VERSION 5.7 ;
BUSBITCHARS "[]" ;
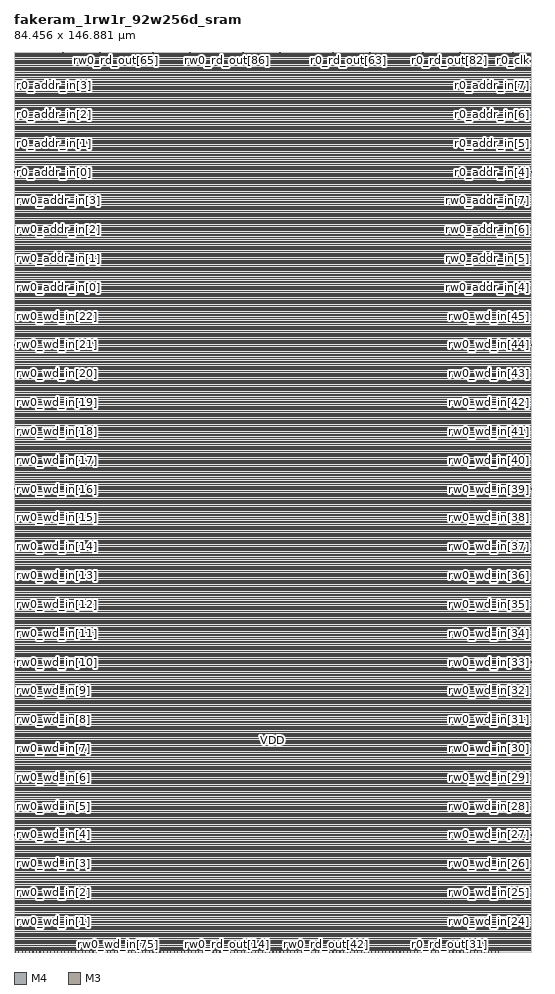
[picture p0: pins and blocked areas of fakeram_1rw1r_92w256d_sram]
MACRO fakeram_1rw1r_92w256d_sram
  FOREIGN fakeram_1rw1r_92w256d_sram 0 0 ;
  SYMMETRY X Y R90 ;
  SIZE 84.456 BY 146.881 ;
  CLASS BLOCK ;
  PIN rw0_wd_in[0]
    DIRECTION INPUT ;
    USE SIGNAL ;
    SHAPE ABUTMENT ;
    PORT
      LAYER M4 ;
      RECT 0.000 0.276 0.072 0.300 ;
    END
  END rw0_wd_in[0]
  PIN rw0_wd_in[1]
    DIRECTION INPUT ;
    USE SIGNAL ;
    SHAPE ABUTMENT ;
    PORT
      LAYER M4 ;
      RECT 0.000 4.980 0.072 5.004 ;
    END
  END rw0_wd_in[1]
  PIN rw0_wd_in[2]
    DIRECTION INPUT ;
    USE SIGNAL ;
    SHAPE ABUTMENT ;
    PORT
      LAYER M4 ;
      RECT 0.000 9.684 0.072 9.708 ;
    END
  END rw0_wd_in[2]
  PIN rw0_wd_in[3]
    DIRECTION INPUT ;
    USE SIGNAL ;
    SHAPE ABUTMENT ;
    PORT
      LAYER M4 ;
      RECT 0.000 14.388 0.072 14.412 ;
    END
  END rw0_wd_in[3]
  PIN rw0_wd_in[4]
    DIRECTION INPUT ;
    USE SIGNAL ;
    SHAPE ABUTMENT ;
    PORT
      LAYER M4 ;
      RECT 0.000 19.092 0.072 19.116 ;
    END
  END rw0_wd_in[4]
  PIN rw0_wd_in[5]
    DIRECTION INPUT ;
    USE SIGNAL ;
    SHAPE ABUTMENT ;
    PORT
      LAYER M4 ;
      RECT 0.000 23.796 0.072 23.820 ;
    END
  END rw0_wd_in[5]
  PIN rw0_wd_in[6]
    DIRECTION INPUT ;
    USE SIGNAL ;
    SHAPE ABUTMENT ;
    PORT
      LAYER M4 ;
      RECT 0.000 28.500 0.072 28.524 ;
    END
  END rw0_wd_in[6]
  PIN rw0_wd_in[7]
    DIRECTION INPUT ;
    USE SIGNAL ;
    SHAPE ABUTMENT ;
    PORT
      LAYER M4 ;
      RECT 0.000 33.204 0.072 33.228 ;
    END
  END rw0_wd_in[7]
  PIN rw0_wd_in[8]
    DIRECTION INPUT ;
    USE SIGNAL ;
    SHAPE ABUTMENT ;
    PORT
      LAYER M4 ;
      RECT 0.000 37.908 0.072 37.932 ;
    END
  END rw0_wd_in[8]
  PIN rw0_wd_in[9]
    DIRECTION INPUT ;
    USE SIGNAL ;
    SHAPE ABUTMENT ;
    PORT
      LAYER M4 ;
      RECT 0.000 42.612 0.072 42.636 ;
    END
  END rw0_wd_in[9]
  PIN rw0_wd_in[10]
    DIRECTION INPUT ;
    USE SIGNAL ;
    SHAPE ABUTMENT ;
    PORT
      LAYER M4 ;
      RECT 0.000 47.316 0.072 47.340 ;
    END
  END rw0_wd_in[10]
  PIN rw0_wd_in[11]
    DIRECTION INPUT ;
    USE SIGNAL ;
    SHAPE ABUTMENT ;
    PORT
      LAYER M4 ;
      RECT 0.000 52.020 0.072 52.044 ;
    END
  END rw0_wd_in[11]
  PIN rw0_wd_in[12]
    DIRECTION INPUT ;
    USE SIGNAL ;
    SHAPE ABUTMENT ;
    PORT
      LAYER M4 ;
      RECT 0.000 56.724 0.072 56.748 ;
    END
  END rw0_wd_in[12]
  PIN rw0_wd_in[13]
    DIRECTION INPUT ;
    USE SIGNAL ;
    SHAPE ABUTMENT ;
    PORT
      LAYER M4 ;
      RECT 0.000 61.428 0.072 61.452 ;
    END
  END rw0_wd_in[13]
  PIN rw0_wd_in[14]
    DIRECTION INPUT ;
    USE SIGNAL ;
    SHAPE ABUTMENT ;
    PORT
      LAYER M4 ;
      RECT 0.000 66.132 0.072 66.156 ;
    END
  END rw0_wd_in[14]
  PIN rw0_wd_in[15]
    DIRECTION INPUT ;
    USE SIGNAL ;
    SHAPE ABUTMENT ;
    PORT
      LAYER M4 ;
      RECT 0.000 70.836 0.072 70.860 ;
    END
  END rw0_wd_in[15]
  PIN rw0_wd_in[16]
    DIRECTION INPUT ;
    USE SIGNAL ;
    SHAPE ABUTMENT ;
    PORT
      LAYER M4 ;
      RECT 0.000 75.540 0.072 75.564 ;
    END
  END rw0_wd_in[16]
  PIN rw0_wd_in[17]
    DIRECTION INPUT ;
    USE SIGNAL ;
    SHAPE ABUTMENT ;
    PORT
      LAYER M4 ;
      RECT 0.000 80.244 0.072 80.268 ;
    END
  END rw0_wd_in[17]
  PIN rw0_wd_in[18]
    DIRECTION INPUT ;
    USE SIGNAL ;
    SHAPE ABUTMENT ;
    PORT
      LAYER M4 ;
      RECT 0.000 84.948 0.072 84.972 ;
    END
  END rw0_wd_in[18]
  PIN rw0_wd_in[19]
    DIRECTION INPUT ;
    USE SIGNAL ;
    SHAPE ABUTMENT ;
    PORT
      LAYER M4 ;
      RECT 0.000 89.652 0.072 89.676 ;
    END
  END rw0_wd_in[19]
  PIN rw0_wd_in[20]
    DIRECTION INPUT ;
    USE SIGNAL ;
    SHAPE ABUTMENT ;
    PORT
      LAYER M4 ;
      RECT 0.000 94.356 0.072 94.380 ;
    END
  END rw0_wd_in[20]
  PIN rw0_wd_in[21]
    DIRECTION INPUT ;
    USE SIGNAL ;
    SHAPE ABUTMENT ;
    PORT
      LAYER M4 ;
      RECT 0.000 99.060 0.072 99.084 ;
    END
  END rw0_wd_in[21]
  PIN rw0_wd_in[22]
    DIRECTION INPUT ;
    USE SIGNAL ;
    SHAPE ABUTMENT ;
    PORT
      LAYER M4 ;
      RECT 0.000 103.764 0.072 103.788 ;
    END
  END rw0_wd_in[22]
  PIN rw0_wd_in[23]
    DIRECTION INPUT ;
    USE SIGNAL ;
    SHAPE ABUTMENT ;
    PORT
      LAYER M4 ;
      RECT 84.384 0.276 84.456 0.300 ;
    END
  END rw0_wd_in[23]
  PIN rw0_wd_in[24]
    DIRECTION INPUT ;
    USE SIGNAL ;
    SHAPE ABUTMENT ;
    PORT
      LAYER M4 ;
      RECT 84.384 4.980 84.456 5.004 ;
    END
  END rw0_wd_in[24]
  PIN rw0_wd_in[25]
    DIRECTION INPUT ;
    USE SIGNAL ;
    SHAPE ABUTMENT ;
    PORT
      LAYER M4 ;
      RECT 84.384 9.684 84.456 9.708 ;
    END
  END rw0_wd_in[25]
  PIN rw0_wd_in[26]
    DIRECTION INPUT ;
    USE SIGNAL ;
    SHAPE ABUTMENT ;
    PORT
      LAYER M4 ;
      RECT 84.384 14.388 84.456 14.412 ;
    END
  END rw0_wd_in[26]
  PIN rw0_wd_in[27]
    DIRECTION INPUT ;
    USE SIGNAL ;
    SHAPE ABUTMENT ;
    PORT
      LAYER M4 ;
      RECT 84.384 19.092 84.456 19.116 ;
    END
  END rw0_wd_in[27]
  PIN rw0_wd_in[28]
    DIRECTION INPUT ;
    USE SIGNAL ;
    SHAPE ABUTMENT ;
    PORT
      LAYER M4 ;
      RECT 84.384 23.796 84.456 23.820 ;
    END
  END rw0_wd_in[28]
  PIN rw0_wd_in[29]
    DIRECTION INPUT ;
    USE SIGNAL ;
    SHAPE ABUTMENT ;
    PORT
      LAYER M4 ;
      RECT 84.384 28.500 84.456 28.524 ;
    END
  END rw0_wd_in[29]
  PIN rw0_wd_in[30]
    DIRECTION INPUT ;
    USE SIGNAL ;
    SHAPE ABUTMENT ;
    PORT
      LAYER M4 ;
      RECT 84.384 33.204 84.456 33.228 ;
    END
  END rw0_wd_in[30]
  PIN rw0_wd_in[31]
    DIRECTION INPUT ;
    USE SIGNAL ;
    SHAPE ABUTMENT ;
    PORT
      LAYER M4 ;
      RECT 84.384 37.908 84.456 37.932 ;
    END
  END rw0_wd_in[31]
  PIN rw0_wd_in[32]
    DIRECTION INPUT ;
    USE SIGNAL ;
    SHAPE ABUTMENT ;
    PORT
      LAYER M4 ;
      RECT 84.384 42.612 84.456 42.636 ;
    END
  END rw0_wd_in[32]
  PIN rw0_wd_in[33]
    DIRECTION INPUT ;
    USE SIGNAL ;
    SHAPE ABUTMENT ;
    PORT
      LAYER M4 ;
      RECT 84.384 47.316 84.456 47.340 ;
    END
  END rw0_wd_in[33]
  PIN rw0_wd_in[34]
    DIRECTION INPUT ;
    USE SIGNAL ;
    SHAPE ABUTMENT ;
    PORT
      LAYER M4 ;
      RECT 84.384 52.020 84.456 52.044 ;
    END
  END rw0_wd_in[34]
  PIN rw0_wd_in[35]
    DIRECTION INPUT ;
    USE SIGNAL ;
    SHAPE ABUTMENT ;
    PORT
      LAYER M4 ;
      RECT 84.384 56.724 84.456 56.748 ;
    END
  END rw0_wd_in[35]
  PIN rw0_wd_in[36]
    DIRECTION INPUT ;
    USE SIGNAL ;
    SHAPE ABUTMENT ;
    PORT
      LAYER M4 ;
      RECT 84.384 61.428 84.456 61.452 ;
    END
  END rw0_wd_in[36]
  PIN rw0_wd_in[37]
    DIRECTION INPUT ;
    USE SIGNAL ;
    SHAPE ABUTMENT ;
    PORT
      LAYER M4 ;
      RECT 84.384 66.132 84.456 66.156 ;
    END
  END rw0_wd_in[37]
  PIN rw0_wd_in[38]
    DIRECTION INPUT ;
    USE SIGNAL ;
    SHAPE ABUTMENT ;
    PORT
      LAYER M4 ;
      RECT 84.384 70.836 84.456 70.860 ;
    END
  END rw0_wd_in[38]
  PIN rw0_wd_in[39]
    DIRECTION INPUT ;
    USE SIGNAL ;
    SHAPE ABUTMENT ;
    PORT
      LAYER M4 ;
      RECT 84.384 75.540 84.456 75.564 ;
    END
  END rw0_wd_in[39]
  PIN rw0_wd_in[40]
    DIRECTION INPUT ;
    USE SIGNAL ;
    SHAPE ABUTMENT ;
    PORT
      LAYER M4 ;
      RECT 84.384 80.244 84.456 80.268 ;
    END
  END rw0_wd_in[40]
  PIN rw0_wd_in[41]
    DIRECTION INPUT ;
    USE SIGNAL ;
    SHAPE ABUTMENT ;
    PORT
      LAYER M4 ;
      RECT 84.384 84.948 84.456 84.972 ;
    END
  END rw0_wd_in[41]
  PIN rw0_wd_in[42]
    DIRECTION INPUT ;
    USE SIGNAL ;
    SHAPE ABUTMENT ;
    PORT
      LAYER M4 ;
      RECT 84.384 89.652 84.456 89.676 ;
    END
  END rw0_wd_in[42]
  PIN rw0_wd_in[43]
    DIRECTION INPUT ;
    USE SIGNAL ;
    SHAPE ABUTMENT ;
    PORT
      LAYER M4 ;
      RECT 84.384 94.356 84.456 94.380 ;
    END
  END rw0_wd_in[43]
  PIN rw0_wd_in[44]
    DIRECTION INPUT ;
    USE SIGNAL ;
    SHAPE ABUTMENT ;
    PORT
      LAYER M4 ;
      RECT 84.384 99.060 84.456 99.084 ;
    END
  END rw0_wd_in[44]
  PIN rw0_wd_in[45]
    DIRECTION INPUT ;
    USE SIGNAL ;
    SHAPE ABUTMENT ;
    PORT
      LAYER M4 ;
      RECT 84.384 103.764 84.456 103.788 ;
    END
  END rw0_wd_in[45]
  PIN rw0_wd_in[46]
    DIRECTION INPUT ;
    USE SIGNAL ;
    SHAPE ABUTMENT ;
    PORT
      LAYER M3 ;
      RECT 0.207 0.000 0.225 0.054 ;
    END
  END rw0_wd_in[46]
  PIN rw0_wd_in[47]
    DIRECTION INPUT ;
    USE SIGNAL ;
    SHAPE ABUTMENT ;
    PORT
      LAYER M3 ;
      RECT 0.783 0.000 0.801 0.054 ;
    END
  END rw0_wd_in[47]
  PIN rw0_wd_in[48]
    DIRECTION INPUT ;
    USE SIGNAL ;
    SHAPE ABUTMENT ;
    PORT
      LAYER M3 ;
      RECT 1.359 0.000 1.377 0.054 ;
    END
  END rw0_wd_in[48]
  PIN rw0_wd_in[49]
    DIRECTION INPUT ;
    USE SIGNAL ;
    SHAPE ABUTMENT ;
    PORT
      LAYER M3 ;
      RECT 1.935 0.000 1.953 0.054 ;
    END
  END rw0_wd_in[49]
  PIN rw0_wd_in[50]
    DIRECTION INPUT ;
    USE SIGNAL ;
    SHAPE ABUTMENT ;
    PORT
      LAYER M3 ;
      RECT 2.511 0.000 2.529 0.054 ;
    END
  END rw0_wd_in[50]
  PIN rw0_wd_in[51]
    DIRECTION INPUT ;
    USE SIGNAL ;
    SHAPE ABUTMENT ;
    PORT
      LAYER M3 ;
      RECT 3.087 0.000 3.105 0.054 ;
    END
  END rw0_wd_in[51]
  PIN rw0_wd_in[52]
    DIRECTION INPUT ;
    USE SIGNAL ;
    SHAPE ABUTMENT ;
    PORT
      LAYER M3 ;
      RECT 3.663 0.000 3.681 0.054 ;
    END
  END rw0_wd_in[52]
  PIN rw0_wd_in[53]
    DIRECTION INPUT ;
    USE SIGNAL ;
    SHAPE ABUTMENT ;
    PORT
      LAYER M3 ;
      RECT 4.239 0.000 4.257 0.054 ;
    END
  END rw0_wd_in[53]
  PIN rw0_wd_in[54]
    DIRECTION INPUT ;
    USE SIGNAL ;
    SHAPE ABUTMENT ;
    PORT
      LAYER M3 ;
      RECT 4.815 0.000 4.833 0.054 ;
    END
  END rw0_wd_in[54]
  PIN rw0_wd_in[55]
    DIRECTION INPUT ;
    USE SIGNAL ;
    SHAPE ABUTMENT ;
    PORT
      LAYER M3 ;
      RECT 5.391 0.000 5.409 0.054 ;
    END
  END rw0_wd_in[55]
  PIN rw0_wd_in[56]
    DIRECTION INPUT ;
    USE SIGNAL ;
    SHAPE ABUTMENT ;
    PORT
      LAYER M3 ;
      RECT 5.967 0.000 5.985 0.054 ;
    END
  END rw0_wd_in[56]
  PIN rw0_wd_in[57]
    DIRECTION INPUT ;
    USE SIGNAL ;
    SHAPE ABUTMENT ;
    PORT
      LAYER M3 ;
      RECT 6.543 0.000 6.561 0.054 ;
    END
  END rw0_wd_in[57]
  PIN rw0_wd_in[58]
    DIRECTION INPUT ;
    USE SIGNAL ;
    SHAPE ABUTMENT ;
    PORT
      LAYER M3 ;
      RECT 7.119 0.000 7.137 0.054 ;
    END
  END rw0_wd_in[58]
  PIN rw0_wd_in[59]
    DIRECTION INPUT ;
    USE SIGNAL ;
    SHAPE ABUTMENT ;
    PORT
      LAYER M3 ;
      RECT 7.695 0.000 7.713 0.054 ;
    END
  END rw0_wd_in[59]
  PIN rw0_wd_in[60]
    DIRECTION INPUT ;
    USE SIGNAL ;
    SHAPE ABUTMENT ;
    PORT
      LAYER M3 ;
      RECT 8.271 0.000 8.289 0.054 ;
    END
  END rw0_wd_in[60]
  PIN rw0_wd_in[61]
    DIRECTION INPUT ;
    USE SIGNAL ;
    SHAPE ABUTMENT ;
    PORT
      LAYER M3 ;
      RECT 8.847 0.000 8.865 0.054 ;
    END
  END rw0_wd_in[61]
  PIN rw0_wd_in[62]
    DIRECTION INPUT ;
    USE SIGNAL ;
    SHAPE ABUTMENT ;
    PORT
      LAYER M3 ;
      RECT 9.423 0.000 9.441 0.054 ;
    END
  END rw0_wd_in[62]
  PIN rw0_wd_in[63]
    DIRECTION INPUT ;
    USE SIGNAL ;
    SHAPE ABUTMENT ;
    PORT
      LAYER M3 ;
      RECT 9.999 0.000 10.017 0.054 ;
    END
  END rw0_wd_in[63]
  PIN rw0_wd_in[64]
    DIRECTION INPUT ;
    USE SIGNAL ;
    SHAPE ABUTMENT ;
    PORT
      LAYER M3 ;
      RECT 10.575 0.000 10.593 0.054 ;
    END
  END rw0_wd_in[64]
  PIN rw0_wd_in[65]
    DIRECTION INPUT ;
    USE SIGNAL ;
    SHAPE ABUTMENT ;
    PORT
      LAYER M3 ;
      RECT 11.151 0.000 11.169 0.054 ;
    END
  END rw0_wd_in[65]
  PIN rw0_wd_in[66]
    DIRECTION INPUT ;
    USE SIGNAL ;
    SHAPE ABUTMENT ;
    PORT
      LAYER M3 ;
      RECT 11.727 0.000 11.745 0.054 ;
    END
  END rw0_wd_in[66]
  PIN rw0_wd_in[67]
    DIRECTION INPUT ;
    USE SIGNAL ;
    SHAPE ABUTMENT ;
    PORT
      LAYER M3 ;
      RECT 12.303 0.000 12.321 0.054 ;
    END
  END rw0_wd_in[67]
  PIN rw0_wd_in[68]
    DIRECTION INPUT ;
    USE SIGNAL ;
    SHAPE ABUTMENT ;
    PORT
      LAYER M3 ;
      RECT 12.879 0.000 12.897 0.054 ;
    END
  END rw0_wd_in[68]
  PIN rw0_wd_in[69]
    DIRECTION INPUT ;
    USE SIGNAL ;
    SHAPE ABUTMENT ;
    PORT
      LAYER M3 ;
      RECT 13.455 0.000 13.473 0.054 ;
    END
  END rw0_wd_in[69]
  PIN rw0_wd_in[70]
    DIRECTION INPUT ;
    USE SIGNAL ;
    SHAPE ABUTMENT ;
    PORT
      LAYER M3 ;
      RECT 14.031 0.000 14.049 0.054 ;
    END
  END rw0_wd_in[70]
  PIN rw0_wd_in[71]
    DIRECTION INPUT ;
    USE SIGNAL ;
    SHAPE ABUTMENT ;
    PORT
      LAYER M3 ;
      RECT 14.607 0.000 14.625 0.054 ;
    END
  END rw0_wd_in[71]
  PIN rw0_wd_in[72]
    DIRECTION INPUT ;
    USE SIGNAL ;
    SHAPE ABUTMENT ;
    PORT
      LAYER M3 ;
      RECT 15.183 0.000 15.201 0.054 ;
    END
  END rw0_wd_in[72]
  PIN rw0_wd_in[73]
    DIRECTION INPUT ;
    USE SIGNAL ;
    SHAPE ABUTMENT ;
    PORT
      LAYER M3 ;
      RECT 15.759 0.000 15.777 0.054 ;
    END
  END rw0_wd_in[73]
  PIN rw0_wd_in[74]
    DIRECTION INPUT ;
    USE SIGNAL ;
    SHAPE ABUTMENT ;
    PORT
      LAYER M3 ;
      RECT 16.335 0.000 16.353 0.054 ;
    END
  END rw0_wd_in[74]
  PIN rw0_wd_in[75]
    DIRECTION INPUT ;
    USE SIGNAL ;
    SHAPE ABUTMENT ;
    PORT
      LAYER M3 ;
      RECT 16.911 0.000 16.929 0.054 ;
    END
  END rw0_wd_in[75]
  PIN rw0_wd_in[76]
    DIRECTION INPUT ;
    USE SIGNAL ;
    SHAPE ABUTMENT ;
    PORT
      LAYER M3 ;
      RECT 17.487 0.000 17.505 0.054 ;
    END
  END rw0_wd_in[76]
  PIN rw0_wd_in[77]
    DIRECTION INPUT ;
    USE SIGNAL ;
    SHAPE ABUTMENT ;
    PORT
      LAYER M3 ;
      RECT 18.063 0.000 18.081 0.054 ;
    END
  END rw0_wd_in[77]
  PIN rw0_wd_in[78]
    DIRECTION INPUT ;
    USE SIGNAL ;
    SHAPE ABUTMENT ;
    PORT
      LAYER M3 ;
      RECT 18.639 0.000 18.657 0.054 ;
    END
  END rw0_wd_in[78]
  PIN rw0_wd_in[79]
    DIRECTION INPUT ;
    USE SIGNAL ;
    SHAPE ABUTMENT ;
    PORT
      LAYER M3 ;
      RECT 19.215 0.000 19.233 0.054 ;
    END
  END rw0_wd_in[79]
  PIN rw0_wd_in[80]
    DIRECTION INPUT ;
    USE SIGNAL ;
    SHAPE ABUTMENT ;
    PORT
      LAYER M3 ;
      RECT 19.791 0.000 19.809 0.054 ;
    END
  END rw0_wd_in[80]
  PIN rw0_wd_in[81]
    DIRECTION INPUT ;
    USE SIGNAL ;
    SHAPE ABUTMENT ;
    PORT
      LAYER M3 ;
      RECT 20.367 0.000 20.385 0.054 ;
    END
  END rw0_wd_in[81]
  PIN rw0_wd_in[82]
    DIRECTION INPUT ;
    USE SIGNAL ;
    SHAPE ABUTMENT ;
    PORT
      LAYER M3 ;
      RECT 20.943 0.000 20.961 0.054 ;
    END
  END rw0_wd_in[82]
  PIN rw0_wd_in[83]
    DIRECTION INPUT ;
    USE SIGNAL ;
    SHAPE ABUTMENT ;
    PORT
      LAYER M3 ;
      RECT 21.519 0.000 21.537 0.054 ;
    END
  END rw0_wd_in[83]
  PIN rw0_wd_in[84]
    DIRECTION INPUT ;
    USE SIGNAL ;
    SHAPE ABUTMENT ;
    PORT
      LAYER M3 ;
      RECT 22.095 0.000 22.113 0.054 ;
    END
  END rw0_wd_in[84]
  PIN rw0_wd_in[85]
    DIRECTION INPUT ;
    USE SIGNAL ;
    SHAPE ABUTMENT ;
    PORT
      LAYER M3 ;
      RECT 22.671 0.000 22.689 0.054 ;
    END
  END rw0_wd_in[85]
  PIN rw0_wd_in[86]
    DIRECTION INPUT ;
    USE SIGNAL ;
    SHAPE ABUTMENT ;
    PORT
      LAYER M3 ;
      RECT 23.247 0.000 23.265 0.054 ;
    END
  END rw0_wd_in[86]
  PIN rw0_wd_in[87]
    DIRECTION INPUT ;
    USE SIGNAL ;
    SHAPE ABUTMENT ;
    PORT
      LAYER M3 ;
      RECT 23.823 0.000 23.841 0.054 ;
    END
  END rw0_wd_in[87]
  PIN rw0_wd_in[88]
    DIRECTION INPUT ;
    USE SIGNAL ;
    SHAPE ABUTMENT ;
    PORT
      LAYER M3 ;
      RECT 24.399 0.000 24.417 0.054 ;
    END
  END rw0_wd_in[88]
  PIN rw0_wd_in[89]
    DIRECTION INPUT ;
    USE SIGNAL ;
    SHAPE ABUTMENT ;
    PORT
      LAYER M3 ;
      RECT 24.975 0.000 24.993 0.054 ;
    END
  END rw0_wd_in[89]
  PIN rw0_wd_in[90]
    DIRECTION INPUT ;
    USE SIGNAL ;
    SHAPE ABUTMENT ;
    PORT
      LAYER M3 ;
      RECT 25.551 0.000 25.569 0.054 ;
    END
  END rw0_wd_in[90]
  PIN rw0_wd_in[91]
    DIRECTION INPUT ;
    USE SIGNAL ;
    SHAPE ABUTMENT ;
    PORT
      LAYER M3 ;
      RECT 26.127 0.000 26.145 0.054 ;
    END
  END rw0_wd_in[91]
  PIN rw0_rd_out[0]
    DIRECTION OUTPUT ;
    USE SIGNAL ;
    SHAPE ABUTMENT ;
    PORT
      LAYER M3 ;
      RECT 26.703 0.000 26.721 0.054 ;
    END
  END rw0_rd_out[0]
  PIN rw0_rd_out[1]
    DIRECTION OUTPUT ;
    USE SIGNAL ;
    SHAPE ABUTMENT ;
    PORT
      LAYER M3 ;
      RECT 27.279 0.000 27.297 0.054 ;
    END
  END rw0_rd_out[1]
  PIN rw0_rd_out[2]
    DIRECTION OUTPUT ;
    USE SIGNAL ;
    SHAPE ABUTMENT ;
    PORT
      LAYER M3 ;
      RECT 27.855 0.000 27.873 0.054 ;
    END
  END rw0_rd_out[2]
  PIN rw0_rd_out[3]
    DIRECTION OUTPUT ;
    USE SIGNAL ;
    SHAPE ABUTMENT ;
    PORT
      LAYER M3 ;
      RECT 28.431 0.000 28.449 0.054 ;
    END
  END rw0_rd_out[3]
  PIN rw0_rd_out[4]
    DIRECTION OUTPUT ;
    USE SIGNAL ;
    SHAPE ABUTMENT ;
    PORT
      LAYER M3 ;
      RECT 29.007 0.000 29.025 0.054 ;
    END
  END rw0_rd_out[4]
  PIN rw0_rd_out[5]
    DIRECTION OUTPUT ;
    USE SIGNAL ;
    SHAPE ABUTMENT ;
    PORT
      LAYER M3 ;
      RECT 29.583 0.000 29.601 0.054 ;
    END
  END rw0_rd_out[5]
  PIN rw0_rd_out[6]
    DIRECTION OUTPUT ;
    USE SIGNAL ;
    SHAPE ABUTMENT ;
    PORT
      LAYER M3 ;
      RECT 30.159 0.000 30.177 0.054 ;
    END
  END rw0_rd_out[6]
  PIN rw0_rd_out[7]
    DIRECTION OUTPUT ;
    USE SIGNAL ;
    SHAPE ABUTMENT ;
    PORT
      LAYER M3 ;
      RECT 30.735 0.000 30.753 0.054 ;
    END
  END rw0_rd_out[7]
  PIN rw0_rd_out[8]
    DIRECTION OUTPUT ;
    USE SIGNAL ;
    SHAPE ABUTMENT ;
    PORT
      LAYER M3 ;
      RECT 31.311 0.000 31.329 0.054 ;
    END
  END rw0_rd_out[8]
  PIN rw0_rd_out[9]
    DIRECTION OUTPUT ;
    USE SIGNAL ;
    SHAPE ABUTMENT ;
    PORT
      LAYER M3 ;
      RECT 31.887 0.000 31.905 0.054 ;
    END
  END rw0_rd_out[9]
  PIN rw0_rd_out[10]
    DIRECTION OUTPUT ;
    USE SIGNAL ;
    SHAPE ABUTMENT ;
    PORT
      LAYER M3 ;
      RECT 32.463 0.000 32.481 0.054 ;
    END
  END rw0_rd_out[10]
  PIN rw0_rd_out[11]
    DIRECTION OUTPUT ;
    USE SIGNAL ;
    SHAPE ABUTMENT ;
    PORT
      LAYER M3 ;
      RECT 33.039 0.000 33.057 0.054 ;
    END
  END rw0_rd_out[11]
  PIN rw0_rd_out[12]
    DIRECTION OUTPUT ;
    USE SIGNAL ;
    SHAPE ABUTMENT ;
    PORT
      LAYER M3 ;
      RECT 33.615 0.000 33.633 0.054 ;
    END
  END rw0_rd_out[12]
  PIN rw0_rd_out[13]
    DIRECTION OUTPUT ;
    USE SIGNAL ;
    SHAPE ABUTMENT ;
    PORT
      LAYER M3 ;
      RECT 34.191 0.000 34.209 0.054 ;
    END
  END rw0_rd_out[13]
  PIN rw0_rd_out[14]
    DIRECTION OUTPUT ;
    USE SIGNAL ;
    SHAPE ABUTMENT ;
    PORT
      LAYER M3 ;
      RECT 34.767 0.000 34.785 0.054 ;
    END
  END rw0_rd_out[14]
  PIN rw0_rd_out[15]
    DIRECTION OUTPUT ;
    USE SIGNAL ;
    SHAPE ABUTMENT ;
    PORT
      LAYER M3 ;
      RECT 35.343 0.000 35.361 0.054 ;
    END
  END rw0_rd_out[15]
  PIN rw0_rd_out[16]
    DIRECTION OUTPUT ;
    USE SIGNAL ;
    SHAPE ABUTMENT ;
    PORT
      LAYER M3 ;
      RECT 35.919 0.000 35.937 0.054 ;
    END
  END rw0_rd_out[16]
  PIN rw0_rd_out[17]
    DIRECTION OUTPUT ;
    USE SIGNAL ;
    SHAPE ABUTMENT ;
    PORT
      LAYER M3 ;
      RECT 36.495 0.000 36.513 0.054 ;
    END
  END rw0_rd_out[17]
  PIN rw0_rd_out[18]
    DIRECTION OUTPUT ;
    USE SIGNAL ;
    SHAPE ABUTMENT ;
    PORT
      LAYER M3 ;
      RECT 37.071 0.000 37.089 0.054 ;
    END
  END rw0_rd_out[18]
  PIN rw0_rd_out[19]
    DIRECTION OUTPUT ;
    USE SIGNAL ;
    SHAPE ABUTMENT ;
    PORT
      LAYER M3 ;
      RECT 37.647 0.000 37.665 0.054 ;
    END
  END rw0_rd_out[19]
  PIN rw0_rd_out[20]
    DIRECTION OUTPUT ;
    USE SIGNAL ;
    SHAPE ABUTMENT ;
    PORT
      LAYER M3 ;
      RECT 38.223 0.000 38.241 0.054 ;
    END
  END rw0_rd_out[20]
  PIN rw0_rd_out[21]
    DIRECTION OUTPUT ;
    USE SIGNAL ;
    SHAPE ABUTMENT ;
    PORT
      LAYER M3 ;
      RECT 38.799 0.000 38.817 0.054 ;
    END
  END rw0_rd_out[21]
  PIN rw0_rd_out[22]
    DIRECTION OUTPUT ;
    USE SIGNAL ;
    SHAPE ABUTMENT ;
    PORT
      LAYER M3 ;
      RECT 39.375 0.000 39.393 0.054 ;
    END
  END rw0_rd_out[22]
  PIN rw0_rd_out[23]
    DIRECTION OUTPUT ;
    USE SIGNAL ;
    SHAPE ABUTMENT ;
    PORT
      LAYER M3 ;
      RECT 39.951 0.000 39.969 0.054 ;
    END
  END rw0_rd_out[23]
  PIN rw0_rd_out[24]
    DIRECTION OUTPUT ;
    USE SIGNAL ;
    SHAPE ABUTMENT ;
    PORT
      LAYER M3 ;
      RECT 40.527 0.000 40.545 0.054 ;
    END
  END rw0_rd_out[24]
  PIN rw0_rd_out[25]
    DIRECTION OUTPUT ;
    USE SIGNAL ;
    SHAPE ABUTMENT ;
    PORT
      LAYER M3 ;
      RECT 41.103 0.000 41.121 0.054 ;
    END
  END rw0_rd_out[25]
  PIN rw0_rd_out[26]
    DIRECTION OUTPUT ;
    USE SIGNAL ;
    SHAPE ABUTMENT ;
    PORT
      LAYER M3 ;
      RECT 41.679 0.000 41.697 0.054 ;
    END
  END rw0_rd_out[26]
  PIN rw0_rd_out[27]
    DIRECTION OUTPUT ;
    USE SIGNAL ;
    SHAPE ABUTMENT ;
    PORT
      LAYER M3 ;
      RECT 42.255 0.000 42.273 0.054 ;
    END
  END rw0_rd_out[27]
  PIN rw0_rd_out[28]
    DIRECTION OUTPUT ;
    USE SIGNAL ;
    SHAPE ABUTMENT ;
    PORT
      LAYER M3 ;
      RECT 42.831 0.000 42.849 0.054 ;
    END
  END rw0_rd_out[28]
  PIN rw0_rd_out[29]
    DIRECTION OUTPUT ;
    USE SIGNAL ;
    SHAPE ABUTMENT ;
    PORT
      LAYER M3 ;
      RECT 43.407 0.000 43.425 0.054 ;
    END
  END rw0_rd_out[29]
  PIN rw0_rd_out[30]
    DIRECTION OUTPUT ;
    USE SIGNAL ;
    SHAPE ABUTMENT ;
    PORT
      LAYER M3 ;
      RECT 43.983 0.000 44.001 0.054 ;
    END
  END rw0_rd_out[30]
  PIN rw0_rd_out[31]
    DIRECTION OUTPUT ;
    USE SIGNAL ;
    SHAPE ABUTMENT ;
    PORT
      LAYER M3 ;
      RECT 44.559 0.000 44.577 0.054 ;
    END
  END rw0_rd_out[31]
  PIN rw0_rd_out[32]
    DIRECTION OUTPUT ;
    USE SIGNAL ;
    SHAPE ABUTMENT ;
    PORT
      LAYER M3 ;
      RECT 45.135 0.000 45.153 0.054 ;
    END
  END rw0_rd_out[32]
  PIN rw0_rd_out[33]
    DIRECTION OUTPUT ;
    USE SIGNAL ;
    SHAPE ABUTMENT ;
    PORT
      LAYER M3 ;
      RECT 45.711 0.000 45.729 0.054 ;
    END
  END rw0_rd_out[33]
  PIN rw0_rd_out[34]
    DIRECTION OUTPUT ;
    USE SIGNAL ;
    SHAPE ABUTMENT ;
    PORT
      LAYER M3 ;
      RECT 46.287 0.000 46.305 0.054 ;
    END
  END rw0_rd_out[34]
  PIN rw0_rd_out[35]
    DIRECTION OUTPUT ;
    USE SIGNAL ;
    SHAPE ABUTMENT ;
    PORT
      LAYER M3 ;
      RECT 46.863 0.000 46.881 0.054 ;
    END
  END rw0_rd_out[35]
  PIN rw0_rd_out[36]
    DIRECTION OUTPUT ;
    USE SIGNAL ;
    SHAPE ABUTMENT ;
    PORT
      LAYER M3 ;
      RECT 47.439 0.000 47.457 0.054 ;
    END
  END rw0_rd_out[36]
  PIN rw0_rd_out[37]
    DIRECTION OUTPUT ;
    USE SIGNAL ;
    SHAPE ABUTMENT ;
    PORT
      LAYER M3 ;
      RECT 48.015 0.000 48.033 0.054 ;
    END
  END rw0_rd_out[37]
  PIN rw0_rd_out[38]
    DIRECTION OUTPUT ;
    USE SIGNAL ;
    SHAPE ABUTMENT ;
    PORT
      LAYER M3 ;
      RECT 48.591 0.000 48.609 0.054 ;
    END
  END rw0_rd_out[38]
  PIN rw0_rd_out[39]
    DIRECTION OUTPUT ;
    USE SIGNAL ;
    SHAPE ABUTMENT ;
    PORT
      LAYER M3 ;
      RECT 49.167 0.000 49.185 0.054 ;
    END
  END rw0_rd_out[39]
  PIN rw0_rd_out[40]
    DIRECTION OUTPUT ;
    USE SIGNAL ;
    SHAPE ABUTMENT ;
    PORT
      LAYER M3 ;
      RECT 49.743 0.000 49.761 0.054 ;
    END
  END rw0_rd_out[40]
  PIN rw0_rd_out[41]
    DIRECTION OUTPUT ;
    USE SIGNAL ;
    SHAPE ABUTMENT ;
    PORT
      LAYER M3 ;
      RECT 50.319 0.000 50.337 0.054 ;
    END
  END rw0_rd_out[41]
  PIN rw0_rd_out[42]
    DIRECTION OUTPUT ;
    USE SIGNAL ;
    SHAPE ABUTMENT ;
    PORT
      LAYER M3 ;
      RECT 50.895 0.000 50.913 0.054 ;
    END
  END rw0_rd_out[42]
  PIN rw0_rd_out[43]
    DIRECTION OUTPUT ;
    USE SIGNAL ;
    SHAPE ABUTMENT ;
    PORT
      LAYER M3 ;
      RECT 51.471 0.000 51.489 0.054 ;
    END
  END rw0_rd_out[43]
  PIN rw0_rd_out[44]
    DIRECTION OUTPUT ;
    USE SIGNAL ;
    SHAPE ABUTMENT ;
    PORT
      LAYER M3 ;
      RECT 52.047 0.000 52.065 0.054 ;
    END
  END rw0_rd_out[44]
  PIN rw0_rd_out[45]
    DIRECTION OUTPUT ;
    USE SIGNAL ;
    SHAPE ABUTMENT ;
    PORT
      LAYER M3 ;
      RECT 52.623 0.000 52.641 0.054 ;
    END
  END rw0_rd_out[45]
  PIN rw0_rd_out[46]
    DIRECTION OUTPUT ;
    USE SIGNAL ;
    SHAPE ABUTMENT ;
    PORT
      LAYER M3 ;
      RECT 0.207 146.827 0.225 146.881 ;
    END
  END rw0_rd_out[46]
  PIN rw0_rd_out[47]
    DIRECTION OUTPUT ;
    USE SIGNAL ;
    SHAPE ABUTMENT ;
    PORT
      LAYER M3 ;
      RECT 1.071 146.827 1.089 146.881 ;
    END
  END rw0_rd_out[47]
  PIN rw0_rd_out[48]
    DIRECTION OUTPUT ;
    USE SIGNAL ;
    SHAPE ABUTMENT ;
    PORT
      LAYER M3 ;
      RECT 1.935 146.827 1.953 146.881 ;
    END
  END rw0_rd_out[48]
  PIN rw0_rd_out[49]
    DIRECTION OUTPUT ;
    USE SIGNAL ;
    SHAPE ABUTMENT ;
    PORT
      LAYER M3 ;
      RECT 2.799 146.827 2.817 146.881 ;
    END
  END rw0_rd_out[49]
  PIN rw0_rd_out[50]
    DIRECTION OUTPUT ;
    USE SIGNAL ;
    SHAPE ABUTMENT ;
    PORT
      LAYER M3 ;
      RECT 3.663 146.827 3.681 146.881 ;
    END
  END rw0_rd_out[50]
  PIN rw0_rd_out[51]
    DIRECTION OUTPUT ;
    USE SIGNAL ;
    SHAPE ABUTMENT ;
    PORT
      LAYER M3 ;
      RECT 4.527 146.827 4.545 146.881 ;
    END
  END rw0_rd_out[51]
  PIN rw0_rd_out[52]
    DIRECTION OUTPUT ;
    USE SIGNAL ;
    SHAPE ABUTMENT ;
    PORT
      LAYER M3 ;
      RECT 5.391 146.827 5.409 146.881 ;
    END
  END rw0_rd_out[52]
  PIN rw0_rd_out[53]
    DIRECTION OUTPUT ;
    USE SIGNAL ;
    SHAPE ABUTMENT ;
    PORT
      LAYER M3 ;
      RECT 6.255 146.827 6.273 146.881 ;
    END
  END rw0_rd_out[53]
  PIN rw0_rd_out[54]
    DIRECTION OUTPUT ;
    USE SIGNAL ;
    SHAPE ABUTMENT ;
    PORT
      LAYER M3 ;
      RECT 7.119 146.827 7.137 146.881 ;
    END
  END rw0_rd_out[54]
  PIN rw0_rd_out[55]
    DIRECTION OUTPUT ;
    USE SIGNAL ;
    SHAPE ABUTMENT ;
    PORT
      LAYER M3 ;
      RECT 7.983 146.827 8.001 146.881 ;
    END
  END rw0_rd_out[55]
  PIN rw0_rd_out[56]
    DIRECTION OUTPUT ;
    USE SIGNAL ;
    SHAPE ABUTMENT ;
    PORT
      LAYER M3 ;
      RECT 8.847 146.827 8.865 146.881 ;
    END
  END rw0_rd_out[56]
  PIN rw0_rd_out[57]
    DIRECTION OUTPUT ;
    USE SIGNAL ;
    SHAPE ABUTMENT ;
    PORT
      LAYER M3 ;
      RECT 9.711 146.827 9.729 146.881 ;
    END
  END rw0_rd_out[57]
  PIN rw0_rd_out[58]
    DIRECTION OUTPUT ;
    USE SIGNAL ;
    SHAPE ABUTMENT ;
    PORT
      LAYER M3 ;
      RECT 10.575 146.827 10.593 146.881 ;
    END
  END rw0_rd_out[58]
  PIN rw0_rd_out[59]
    DIRECTION OUTPUT ;
    USE SIGNAL ;
    SHAPE ABUTMENT ;
    PORT
      LAYER M3 ;
      RECT 11.439 146.827 11.457 146.881 ;
    END
  END rw0_rd_out[59]
  PIN rw0_rd_out[60]
    DIRECTION OUTPUT ;
    USE SIGNAL ;
    SHAPE ABUTMENT ;
    PORT
      LAYER M3 ;
      RECT 12.303 146.827 12.321 146.881 ;
    END
  END rw0_rd_out[60]
  PIN rw0_rd_out[61]
    DIRECTION OUTPUT ;
    USE SIGNAL ;
    SHAPE ABUTMENT ;
    PORT
      LAYER M3 ;
      RECT 13.167 146.827 13.185 146.881 ;
    END
  END rw0_rd_out[61]
  PIN rw0_rd_out[62]
    DIRECTION OUTPUT ;
    USE SIGNAL ;
    SHAPE ABUTMENT ;
    PORT
      LAYER M3 ;
      RECT 14.031 146.827 14.049 146.881 ;
    END
  END rw0_rd_out[62]
  PIN rw0_rd_out[63]
    DIRECTION OUTPUT ;
    USE SIGNAL ;
    SHAPE ABUTMENT ;
    PORT
      LAYER M3 ;
      RECT 14.895 146.827 14.913 146.881 ;
    END
  END rw0_rd_out[63]
  PIN rw0_rd_out[64]
    DIRECTION OUTPUT ;
    USE SIGNAL ;
    SHAPE ABUTMENT ;
    PORT
      LAYER M3 ;
      RECT 15.759 146.827 15.777 146.881 ;
    END
  END rw0_rd_out[64]
  PIN rw0_rd_out[65]
    DIRECTION OUTPUT ;
    USE SIGNAL ;
    SHAPE ABUTMENT ;
    PORT
      LAYER M3 ;
      RECT 16.623 146.827 16.641 146.881 ;
    END
  END rw0_rd_out[65]
  PIN rw0_rd_out[66]
    DIRECTION OUTPUT ;
    USE SIGNAL ;
    SHAPE ABUTMENT ;
    PORT
      LAYER M3 ;
      RECT 17.487 146.827 17.505 146.881 ;
    END
  END rw0_rd_out[66]
  PIN rw0_rd_out[67]
    DIRECTION OUTPUT ;
    USE SIGNAL ;
    SHAPE ABUTMENT ;
    PORT
      LAYER M3 ;
      RECT 18.351 146.827 18.369 146.881 ;
    END
  END rw0_rd_out[67]
  PIN rw0_rd_out[68]
    DIRECTION OUTPUT ;
    USE SIGNAL ;
    SHAPE ABUTMENT ;
    PORT
      LAYER M3 ;
      RECT 19.215 146.827 19.233 146.881 ;
    END
  END rw0_rd_out[68]
  PIN rw0_rd_out[69]
    DIRECTION OUTPUT ;
    USE SIGNAL ;
    SHAPE ABUTMENT ;
    PORT
      LAYER M3 ;
      RECT 20.079 146.827 20.097 146.881 ;
    END
  END rw0_rd_out[69]
  PIN rw0_rd_out[70]
    DIRECTION OUTPUT ;
    USE SIGNAL ;
    SHAPE ABUTMENT ;
    PORT
      LAYER M3 ;
      RECT 20.943 146.827 20.961 146.881 ;
    END
  END rw0_rd_out[70]
  PIN rw0_rd_out[71]
    DIRECTION OUTPUT ;
    USE SIGNAL ;
    SHAPE ABUTMENT ;
    PORT
      LAYER M3 ;
      RECT 21.807 146.827 21.825 146.881 ;
    END
  END rw0_rd_out[71]
  PIN rw0_rd_out[72]
    DIRECTION OUTPUT ;
    USE SIGNAL ;
    SHAPE ABUTMENT ;
    PORT
      LAYER M3 ;
      RECT 22.671 146.827 22.689 146.881 ;
    END
  END rw0_rd_out[72]
  PIN rw0_rd_out[73]
    DIRECTION OUTPUT ;
    USE SIGNAL ;
    SHAPE ABUTMENT ;
    PORT
      LAYER M3 ;
      RECT 23.535 146.827 23.553 146.881 ;
    END
  END rw0_rd_out[73]
  PIN rw0_rd_out[74]
    DIRECTION OUTPUT ;
    USE SIGNAL ;
    SHAPE ABUTMENT ;
    PORT
      LAYER M3 ;
      RECT 24.399 146.827 24.417 146.881 ;
    END
  END rw0_rd_out[74]
  PIN rw0_rd_out[75]
    DIRECTION OUTPUT ;
    USE SIGNAL ;
    SHAPE ABUTMENT ;
    PORT
      LAYER M3 ;
      RECT 25.263 146.827 25.281 146.881 ;
    END
  END rw0_rd_out[75]
  PIN rw0_rd_out[76]
    DIRECTION OUTPUT ;
    USE SIGNAL ;
    SHAPE ABUTMENT ;
    PORT
      LAYER M3 ;
      RECT 26.127 146.827 26.145 146.881 ;
    END
  END rw0_rd_out[76]
  PIN rw0_rd_out[77]
    DIRECTION OUTPUT ;
    USE SIGNAL ;
    SHAPE ABUTMENT ;
    PORT
      LAYER M3 ;
      RECT 26.991 146.827 27.009 146.881 ;
    END
  END rw0_rd_out[77]
  PIN rw0_rd_out[78]
    DIRECTION OUTPUT ;
    USE SIGNAL ;
    SHAPE ABUTMENT ;
    PORT
      LAYER M3 ;
      RECT 27.855 146.827 27.873 146.881 ;
    END
  END rw0_rd_out[78]
  PIN rw0_rd_out[79]
    DIRECTION OUTPUT ;
    USE SIGNAL ;
    SHAPE ABUTMENT ;
    PORT
      LAYER M3 ;
      RECT 28.719 146.827 28.737 146.881 ;
    END
  END rw0_rd_out[79]
  PIN rw0_rd_out[80]
    DIRECTION OUTPUT ;
    USE SIGNAL ;
    SHAPE ABUTMENT ;
    PORT
      LAYER M3 ;
      RECT 29.583 146.827 29.601 146.881 ;
    END
  END rw0_rd_out[80]
  PIN rw0_rd_out[81]
    DIRECTION OUTPUT ;
    USE SIGNAL ;
    SHAPE ABUTMENT ;
    PORT
      LAYER M3 ;
      RECT 30.447 146.827 30.465 146.881 ;
    END
  END rw0_rd_out[81]
  PIN rw0_rd_out[82]
    DIRECTION OUTPUT ;
    USE SIGNAL ;
    SHAPE ABUTMENT ;
    PORT
      LAYER M3 ;
      RECT 31.311 146.827 31.329 146.881 ;
    END
  END rw0_rd_out[82]
  PIN rw0_rd_out[83]
    DIRECTION OUTPUT ;
    USE SIGNAL ;
    SHAPE ABUTMENT ;
    PORT
      LAYER M3 ;
      RECT 32.175 146.827 32.193 146.881 ;
    END
  END rw0_rd_out[83]
  PIN rw0_rd_out[84]
    DIRECTION OUTPUT ;
    USE SIGNAL ;
    SHAPE ABUTMENT ;
    PORT
      LAYER M3 ;
      RECT 33.039 146.827 33.057 146.881 ;
    END
  END rw0_rd_out[84]
  PIN rw0_rd_out[85]
    DIRECTION OUTPUT ;
    USE SIGNAL ;
    SHAPE ABUTMENT ;
    PORT
      LAYER M3 ;
      RECT 33.903 146.827 33.921 146.881 ;
    END
  END rw0_rd_out[85]
  PIN rw0_rd_out[86]
    DIRECTION OUTPUT ;
    USE SIGNAL ;
    SHAPE ABUTMENT ;
    PORT
      LAYER M3 ;
      RECT 34.767 146.827 34.785 146.881 ;
    END
  END rw0_rd_out[86]
  PIN rw0_rd_out[87]
    DIRECTION OUTPUT ;
    USE SIGNAL ;
    SHAPE ABUTMENT ;
    PORT
      LAYER M3 ;
      RECT 35.631 146.827 35.649 146.881 ;
    END
  END rw0_rd_out[87]
  PIN rw0_rd_out[88]
    DIRECTION OUTPUT ;
    USE SIGNAL ;
    SHAPE ABUTMENT ;
    PORT
      LAYER M3 ;
      RECT 36.495 146.827 36.513 146.881 ;
    END
  END rw0_rd_out[88]
  PIN rw0_rd_out[89]
    DIRECTION OUTPUT ;
    USE SIGNAL ;
    SHAPE ABUTMENT ;
    PORT
      LAYER M3 ;
      RECT 37.359 146.827 37.377 146.881 ;
    END
  END rw0_rd_out[89]
  PIN rw0_rd_out[90]
    DIRECTION OUTPUT ;
    USE SIGNAL ;
    SHAPE ABUTMENT ;
    PORT
      LAYER M3 ;
      RECT 38.223 146.827 38.241 146.881 ;
    END
  END rw0_rd_out[90]
  PIN rw0_rd_out[91]
    DIRECTION OUTPUT ;
    USE SIGNAL ;
    SHAPE ABUTMENT ;
    PORT
      LAYER M3 ;
      RECT 39.087 146.827 39.105 146.881 ;
    END
  END rw0_rd_out[91]
  PIN r0_rd_out[0]
    DIRECTION OUTPUT ;
    USE SIGNAL ;
    SHAPE ABUTMENT ;
    PORT
      LAYER M3 ;
      RECT 53.199 0.000 53.217 0.054 ;
    END
  END r0_rd_out[0]
  PIN r0_rd_out[1]
    DIRECTION OUTPUT ;
    USE SIGNAL ;
    SHAPE ABUTMENT ;
    PORT
      LAYER M3 ;
      RECT 53.775 0.000 53.793 0.054 ;
    END
  END r0_rd_out[1]
  PIN r0_rd_out[2]
    DIRECTION OUTPUT ;
    USE SIGNAL ;
    SHAPE ABUTMENT ;
    PORT
      LAYER M3 ;
      RECT 54.351 0.000 54.369 0.054 ;
    END
  END r0_rd_out[2]
  PIN r0_rd_out[3]
    DIRECTION OUTPUT ;
    USE SIGNAL ;
    SHAPE ABUTMENT ;
    PORT
      LAYER M3 ;
      RECT 54.927 0.000 54.945 0.054 ;
    END
  END r0_rd_out[3]
  PIN r0_rd_out[4]
    DIRECTION OUTPUT ;
    USE SIGNAL ;
    SHAPE ABUTMENT ;
    PORT
      LAYER M3 ;
      RECT 55.503 0.000 55.521 0.054 ;
    END
  END r0_rd_out[4]
  PIN r0_rd_out[5]
    DIRECTION OUTPUT ;
    USE SIGNAL ;
    SHAPE ABUTMENT ;
    PORT
      LAYER M3 ;
      RECT 56.079 0.000 56.097 0.054 ;
    END
  END r0_rd_out[5]
  PIN r0_rd_out[6]
    DIRECTION OUTPUT ;
    USE SIGNAL ;
    SHAPE ABUTMENT ;
    PORT
      LAYER M3 ;
      RECT 56.655 0.000 56.673 0.054 ;
    END
  END r0_rd_out[6]
  PIN r0_rd_out[7]
    DIRECTION OUTPUT ;
    USE SIGNAL ;
    SHAPE ABUTMENT ;
    PORT
      LAYER M3 ;
      RECT 57.231 0.000 57.249 0.054 ;
    END
  END r0_rd_out[7]
  PIN r0_rd_out[8]
    DIRECTION OUTPUT ;
    USE SIGNAL ;
    SHAPE ABUTMENT ;
    PORT
      LAYER M3 ;
      RECT 57.807 0.000 57.825 0.054 ;
    END
  END r0_rd_out[8]
  PIN r0_rd_out[9]
    DIRECTION OUTPUT ;
    USE SIGNAL ;
    SHAPE ABUTMENT ;
    PORT
      LAYER M3 ;
      RECT 58.383 0.000 58.401 0.054 ;
    END
  END r0_rd_out[9]
  PIN r0_rd_out[10]
    DIRECTION OUTPUT ;
    USE SIGNAL ;
    SHAPE ABUTMENT ;
    PORT
      LAYER M3 ;
      RECT 58.959 0.000 58.977 0.054 ;
    END
  END r0_rd_out[10]
  PIN r0_rd_out[11]
    DIRECTION OUTPUT ;
    USE SIGNAL ;
    SHAPE ABUTMENT ;
    PORT
      LAYER M3 ;
      RECT 59.535 0.000 59.553 0.054 ;
    END
  END r0_rd_out[11]
  PIN r0_rd_out[12]
    DIRECTION OUTPUT ;
    USE SIGNAL ;
    SHAPE ABUTMENT ;
    PORT
      LAYER M3 ;
      RECT 60.111 0.000 60.129 0.054 ;
    END
  END r0_rd_out[12]
  PIN r0_rd_out[13]
    DIRECTION OUTPUT ;
    USE SIGNAL ;
    SHAPE ABUTMENT ;
    PORT
      LAYER M3 ;
      RECT 60.687 0.000 60.705 0.054 ;
    END
  END r0_rd_out[13]
  PIN r0_rd_out[14]
    DIRECTION OUTPUT ;
    USE SIGNAL ;
    SHAPE ABUTMENT ;
    PORT
      LAYER M3 ;
      RECT 61.263 0.000 61.281 0.054 ;
    END
  END r0_rd_out[14]
  PIN r0_rd_out[15]
    DIRECTION OUTPUT ;
    USE SIGNAL ;
    SHAPE ABUTMENT ;
    PORT
      LAYER M3 ;
      RECT 61.839 0.000 61.857 0.054 ;
    END
  END r0_rd_out[15]
  PIN r0_rd_out[16]
    DIRECTION OUTPUT ;
    USE SIGNAL ;
    SHAPE ABUTMENT ;
    PORT
      LAYER M3 ;
      RECT 62.415 0.000 62.433 0.054 ;
    END
  END r0_rd_out[16]
  PIN r0_rd_out[17]
    DIRECTION OUTPUT ;
    USE SIGNAL ;
    SHAPE ABUTMENT ;
    PORT
      LAYER M3 ;
      RECT 62.991 0.000 63.009 0.054 ;
    END
  END r0_rd_out[17]
  PIN r0_rd_out[18]
    DIRECTION OUTPUT ;
    USE SIGNAL ;
    SHAPE ABUTMENT ;
    PORT
      LAYER M3 ;
      RECT 63.567 0.000 63.585 0.054 ;
    END
  END r0_rd_out[18]
  PIN r0_rd_out[19]
    DIRECTION OUTPUT ;
    USE SIGNAL ;
    SHAPE ABUTMENT ;
    PORT
      LAYER M3 ;
      RECT 64.143 0.000 64.161 0.054 ;
    END
  END r0_rd_out[19]
  PIN r0_rd_out[20]
    DIRECTION OUTPUT ;
    USE SIGNAL ;
    SHAPE ABUTMENT ;
    PORT
      LAYER M3 ;
      RECT 64.719 0.000 64.737 0.054 ;
    END
  END r0_rd_out[20]
  PIN r0_rd_out[21]
    DIRECTION OUTPUT ;
    USE SIGNAL ;
    SHAPE ABUTMENT ;
    PORT
      LAYER M3 ;
      RECT 65.295 0.000 65.313 0.054 ;
    END
  END r0_rd_out[21]
  PIN r0_rd_out[22]
    DIRECTION OUTPUT ;
    USE SIGNAL ;
    SHAPE ABUTMENT ;
    PORT
      LAYER M3 ;
      RECT 65.871 0.000 65.889 0.054 ;
    END
  END r0_rd_out[22]
  PIN r0_rd_out[23]
    DIRECTION OUTPUT ;
    USE SIGNAL ;
    SHAPE ABUTMENT ;
    PORT
      LAYER M3 ;
      RECT 66.447 0.000 66.465 0.054 ;
    END
  END r0_rd_out[23]
  PIN r0_rd_out[24]
    DIRECTION OUTPUT ;
    USE SIGNAL ;
    SHAPE ABUTMENT ;
    PORT
      LAYER M3 ;
      RECT 67.023 0.000 67.041 0.054 ;
    END
  END r0_rd_out[24]
  PIN r0_rd_out[25]
    DIRECTION OUTPUT ;
    USE SIGNAL ;
    SHAPE ABUTMENT ;
    PORT
      LAYER M3 ;
      RECT 67.599 0.000 67.617 0.054 ;
    END
  END r0_rd_out[25]
  PIN r0_rd_out[26]
    DIRECTION OUTPUT ;
    USE SIGNAL ;
    SHAPE ABUTMENT ;
    PORT
      LAYER M3 ;
      RECT 68.175 0.000 68.193 0.054 ;
    END
  END r0_rd_out[26]
  PIN r0_rd_out[27]
    DIRECTION OUTPUT ;
    USE SIGNAL ;
    SHAPE ABUTMENT ;
    PORT
      LAYER M3 ;
      RECT 68.751 0.000 68.769 0.054 ;
    END
  END r0_rd_out[27]
  PIN r0_rd_out[28]
    DIRECTION OUTPUT ;
    USE SIGNAL ;
    SHAPE ABUTMENT ;
    PORT
      LAYER M3 ;
      RECT 69.327 0.000 69.345 0.054 ;
    END
  END r0_rd_out[28]
  PIN r0_rd_out[29]
    DIRECTION OUTPUT ;
    USE SIGNAL ;
    SHAPE ABUTMENT ;
    PORT
      LAYER M3 ;
      RECT 69.903 0.000 69.921 0.054 ;
    END
  END r0_rd_out[29]
  PIN r0_rd_out[30]
    DIRECTION OUTPUT ;
    USE SIGNAL ;
    SHAPE ABUTMENT ;
    PORT
      LAYER M3 ;
      RECT 70.479 0.000 70.497 0.054 ;
    END
  END r0_rd_out[30]
  PIN r0_rd_out[31]
    DIRECTION OUTPUT ;
    USE SIGNAL ;
    SHAPE ABUTMENT ;
    PORT
      LAYER M3 ;
      RECT 71.055 0.000 71.073 0.054 ;
    END
  END r0_rd_out[31]
  PIN r0_rd_out[32]
    DIRECTION OUTPUT ;
    USE SIGNAL ;
    SHAPE ABUTMENT ;
    PORT
      LAYER M3 ;
      RECT 71.631 0.000 71.649 0.054 ;
    END
  END r0_rd_out[32]
  PIN r0_rd_out[33]
    DIRECTION OUTPUT ;
    USE SIGNAL ;
    SHAPE ABUTMENT ;
    PORT
      LAYER M3 ;
      RECT 72.207 0.000 72.225 0.054 ;
    END
  END r0_rd_out[33]
  PIN r0_rd_out[34]
    DIRECTION OUTPUT ;
    USE SIGNAL ;
    SHAPE ABUTMENT ;
    PORT
      LAYER M3 ;
      RECT 72.783 0.000 72.801 0.054 ;
    END
  END r0_rd_out[34]
  PIN r0_rd_out[35]
    DIRECTION OUTPUT ;
    USE SIGNAL ;
    SHAPE ABUTMENT ;
    PORT
      LAYER M3 ;
      RECT 73.359 0.000 73.377 0.054 ;
    END
  END r0_rd_out[35]
  PIN r0_rd_out[36]
    DIRECTION OUTPUT ;
    USE SIGNAL ;
    SHAPE ABUTMENT ;
    PORT
      LAYER M3 ;
      RECT 73.935 0.000 73.953 0.054 ;
    END
  END r0_rd_out[36]
  PIN r0_rd_out[37]
    DIRECTION OUTPUT ;
    USE SIGNAL ;
    SHAPE ABUTMENT ;
    PORT
      LAYER M3 ;
      RECT 74.511 0.000 74.529 0.054 ;
    END
  END r0_rd_out[37]
  PIN r0_rd_out[38]
    DIRECTION OUTPUT ;
    USE SIGNAL ;
    SHAPE ABUTMENT ;
    PORT
      LAYER M3 ;
      RECT 75.087 0.000 75.105 0.054 ;
    END
  END r0_rd_out[38]
  PIN r0_rd_out[39]
    DIRECTION OUTPUT ;
    USE SIGNAL ;
    SHAPE ABUTMENT ;
    PORT
      LAYER M3 ;
      RECT 75.663 0.000 75.681 0.054 ;
    END
  END r0_rd_out[39]
  PIN r0_rd_out[40]
    DIRECTION OUTPUT ;
    USE SIGNAL ;
    SHAPE ABUTMENT ;
    PORT
      LAYER M3 ;
      RECT 76.239 0.000 76.257 0.054 ;
    END
  END r0_rd_out[40]
  PIN r0_rd_out[41]
    DIRECTION OUTPUT ;
    USE SIGNAL ;
    SHAPE ABUTMENT ;
    PORT
      LAYER M3 ;
      RECT 76.815 0.000 76.833 0.054 ;
    END
  END r0_rd_out[41]
  PIN r0_rd_out[42]
    DIRECTION OUTPUT ;
    USE SIGNAL ;
    SHAPE ABUTMENT ;
    PORT
      LAYER M3 ;
      RECT 77.391 0.000 77.409 0.054 ;
    END
  END r0_rd_out[42]
  PIN r0_rd_out[43]
    DIRECTION OUTPUT ;
    USE SIGNAL ;
    SHAPE ABUTMENT ;
    PORT
      LAYER M3 ;
      RECT 77.967 0.000 77.985 0.054 ;
    END
  END r0_rd_out[43]
  PIN r0_rd_out[44]
    DIRECTION OUTPUT ;
    USE SIGNAL ;
    SHAPE ABUTMENT ;
    PORT
      LAYER M3 ;
      RECT 78.543 0.000 78.561 0.054 ;
    END
  END r0_rd_out[44]
  PIN r0_rd_out[45]
    DIRECTION OUTPUT ;
    USE SIGNAL ;
    SHAPE ABUTMENT ;
    PORT
      LAYER M3 ;
      RECT 79.119 0.000 79.137 0.054 ;
    END
  END r0_rd_out[45]
  PIN r0_rd_out[46]
    DIRECTION OUTPUT ;
    USE SIGNAL ;
    SHAPE ABUTMENT ;
    PORT
      LAYER M3 ;
      RECT 39.951 146.827 39.969 146.881 ;
    END
  END r0_rd_out[46]
  PIN r0_rd_out[47]
    DIRECTION OUTPUT ;
    USE SIGNAL ;
    SHAPE ABUTMENT ;
    PORT
      LAYER M3 ;
      RECT 40.815 146.827 40.833 146.881 ;
    END
  END r0_rd_out[47]
  PIN r0_rd_out[48]
    DIRECTION OUTPUT ;
    USE SIGNAL ;
    SHAPE ABUTMENT ;
    PORT
      LAYER M3 ;
      RECT 41.679 146.827 41.697 146.881 ;
    END
  END r0_rd_out[48]
  PIN r0_rd_out[49]
    DIRECTION OUTPUT ;
    USE SIGNAL ;
    SHAPE ABUTMENT ;
    PORT
      LAYER M3 ;
      RECT 42.543 146.827 42.561 146.881 ;
    END
  END r0_rd_out[49]
  PIN r0_rd_out[50]
    DIRECTION OUTPUT ;
    USE SIGNAL ;
    SHAPE ABUTMENT ;
    PORT
      LAYER M3 ;
      RECT 43.407 146.827 43.425 146.881 ;
    END
  END r0_rd_out[50]
  PIN r0_rd_out[51]
    DIRECTION OUTPUT ;
    USE SIGNAL ;
    SHAPE ABUTMENT ;
    PORT
      LAYER M3 ;
      RECT 44.271 146.827 44.289 146.881 ;
    END
  END r0_rd_out[51]
  PIN r0_rd_out[52]
    DIRECTION OUTPUT ;
    USE SIGNAL ;
    SHAPE ABUTMENT ;
    PORT
      LAYER M3 ;
      RECT 45.135 146.827 45.153 146.881 ;
    END
  END r0_rd_out[52]
  PIN r0_rd_out[53]
    DIRECTION OUTPUT ;
    USE SIGNAL ;
    SHAPE ABUTMENT ;
    PORT
      LAYER M3 ;
      RECT 45.999 146.827 46.017 146.881 ;
    END
  END r0_rd_out[53]
  PIN r0_rd_out[54]
    DIRECTION OUTPUT ;
    USE SIGNAL ;
    SHAPE ABUTMENT ;
    PORT
      LAYER M3 ;
      RECT 46.863 146.827 46.881 146.881 ;
    END
  END r0_rd_out[54]
  PIN r0_rd_out[55]
    DIRECTION OUTPUT ;
    USE SIGNAL ;
    SHAPE ABUTMENT ;
    PORT
      LAYER M3 ;
      RECT 47.727 146.827 47.745 146.881 ;
    END
  END r0_rd_out[55]
  PIN r0_rd_out[56]
    DIRECTION OUTPUT ;
    USE SIGNAL ;
    SHAPE ABUTMENT ;
    PORT
      LAYER M3 ;
      RECT 48.591 146.827 48.609 146.881 ;
    END
  END r0_rd_out[56]
  PIN r0_rd_out[57]
    DIRECTION OUTPUT ;
    USE SIGNAL ;
    SHAPE ABUTMENT ;
    PORT
      LAYER M3 ;
      RECT 49.455 146.827 49.473 146.881 ;
    END
  END r0_rd_out[57]
  PIN r0_rd_out[58]
    DIRECTION OUTPUT ;
    USE SIGNAL ;
    SHAPE ABUTMENT ;
    PORT
      LAYER M3 ;
      RECT 50.319 146.827 50.337 146.881 ;
    END
  END r0_rd_out[58]
  PIN r0_rd_out[59]
    DIRECTION OUTPUT ;
    USE SIGNAL ;
    SHAPE ABUTMENT ;
    PORT
      LAYER M3 ;
      RECT 51.183 146.827 51.201 146.881 ;
    END
  END r0_rd_out[59]
  PIN r0_rd_out[60]
    DIRECTION OUTPUT ;
    USE SIGNAL ;
    SHAPE ABUTMENT ;
    PORT
      LAYER M3 ;
      RECT 52.047 146.827 52.065 146.881 ;
    END
  END r0_rd_out[60]
  PIN r0_rd_out[61]
    DIRECTION OUTPUT ;
    USE SIGNAL ;
    SHAPE ABUTMENT ;
    PORT
      LAYER M3 ;
      RECT 52.911 146.827 52.929 146.881 ;
    END
  END r0_rd_out[61]
  PIN r0_rd_out[62]
    DIRECTION OUTPUT ;
    USE SIGNAL ;
    SHAPE ABUTMENT ;
    PORT
      LAYER M3 ;
      RECT 53.775 146.827 53.793 146.881 ;
    END
  END r0_rd_out[62]
  PIN r0_rd_out[63]
    DIRECTION OUTPUT ;
    USE SIGNAL ;
    SHAPE ABUTMENT ;
    PORT
      LAYER M3 ;
      RECT 54.639 146.827 54.657 146.881 ;
    END
  END r0_rd_out[63]
  PIN r0_rd_out[64]
    DIRECTION OUTPUT ;
    USE SIGNAL ;
    SHAPE ABUTMENT ;
    PORT
      LAYER M3 ;
      RECT 55.503 146.827 55.521 146.881 ;
    END
  END r0_rd_out[64]
  PIN r0_rd_out[65]
    DIRECTION OUTPUT ;
    USE SIGNAL ;
    SHAPE ABUTMENT ;
    PORT
      LAYER M3 ;
      RECT 56.367 146.827 56.385 146.881 ;
    END
  END r0_rd_out[65]
  PIN r0_rd_out[66]
    DIRECTION OUTPUT ;
    USE SIGNAL ;
    SHAPE ABUTMENT ;
    PORT
      LAYER M3 ;
      RECT 57.231 146.827 57.249 146.881 ;
    END
  END r0_rd_out[66]
  PIN r0_rd_out[67]
    DIRECTION OUTPUT ;
    USE SIGNAL ;
    SHAPE ABUTMENT ;
    PORT
      LAYER M3 ;
      RECT 58.095 146.827 58.113 146.881 ;
    END
  END r0_rd_out[67]
  PIN r0_rd_out[68]
    DIRECTION OUTPUT ;
    USE SIGNAL ;
    SHAPE ABUTMENT ;
    PORT
      LAYER M3 ;
      RECT 58.959 146.827 58.977 146.881 ;
    END
  END r0_rd_out[68]
  PIN r0_rd_out[69]
    DIRECTION OUTPUT ;
    USE SIGNAL ;
    SHAPE ABUTMENT ;
    PORT
      LAYER M3 ;
      RECT 59.823 146.827 59.841 146.881 ;
    END
  END r0_rd_out[69]
  PIN r0_rd_out[70]
    DIRECTION OUTPUT ;
    USE SIGNAL ;
    SHAPE ABUTMENT ;
    PORT
      LAYER M3 ;
      RECT 60.687 146.827 60.705 146.881 ;
    END
  END r0_rd_out[70]
  PIN r0_rd_out[71]
    DIRECTION OUTPUT ;
    USE SIGNAL ;
    SHAPE ABUTMENT ;
    PORT
      LAYER M3 ;
      RECT 61.551 146.827 61.569 146.881 ;
    END
  END r0_rd_out[71]
  PIN r0_rd_out[72]
    DIRECTION OUTPUT ;
    USE SIGNAL ;
    SHAPE ABUTMENT ;
    PORT
      LAYER M3 ;
      RECT 62.415 146.827 62.433 146.881 ;
    END
  END r0_rd_out[72]
  PIN r0_rd_out[73]
    DIRECTION OUTPUT ;
    USE SIGNAL ;
    SHAPE ABUTMENT ;
    PORT
      LAYER M3 ;
      RECT 63.279 146.827 63.297 146.881 ;
    END
  END r0_rd_out[73]
  PIN r0_rd_out[74]
    DIRECTION OUTPUT ;
    USE SIGNAL ;
    SHAPE ABUTMENT ;
    PORT
      LAYER M3 ;
      RECT 64.143 146.827 64.161 146.881 ;
    END
  END r0_rd_out[74]
  PIN r0_rd_out[75]
    DIRECTION OUTPUT ;
    USE SIGNAL ;
    SHAPE ABUTMENT ;
    PORT
      LAYER M3 ;
      RECT 65.007 146.827 65.025 146.881 ;
    END
  END r0_rd_out[75]
  PIN r0_rd_out[76]
    DIRECTION OUTPUT ;
    USE SIGNAL ;
    SHAPE ABUTMENT ;
    PORT
      LAYER M3 ;
      RECT 65.871 146.827 65.889 146.881 ;
    END
  END r0_rd_out[76]
  PIN r0_rd_out[77]
    DIRECTION OUTPUT ;
    USE SIGNAL ;
    SHAPE ABUTMENT ;
    PORT
      LAYER M3 ;
      RECT 66.735 146.827 66.753 146.881 ;
    END
  END r0_rd_out[77]
  PIN r0_rd_out[78]
    DIRECTION OUTPUT ;
    USE SIGNAL ;
    SHAPE ABUTMENT ;
    PORT
      LAYER M3 ;
      RECT 67.599 146.827 67.617 146.881 ;
    END
  END r0_rd_out[78]
  PIN r0_rd_out[79]
    DIRECTION OUTPUT ;
    USE SIGNAL ;
    SHAPE ABUTMENT ;
    PORT
      LAYER M3 ;
      RECT 68.463 146.827 68.481 146.881 ;
    END
  END r0_rd_out[79]
  PIN r0_rd_out[80]
    DIRECTION OUTPUT ;
    USE SIGNAL ;
    SHAPE ABUTMENT ;
    PORT
      LAYER M3 ;
      RECT 69.327 146.827 69.345 146.881 ;
    END
  END r0_rd_out[80]
  PIN r0_rd_out[81]
    DIRECTION OUTPUT ;
    USE SIGNAL ;
    SHAPE ABUTMENT ;
    PORT
      LAYER M3 ;
      RECT 70.191 146.827 70.209 146.881 ;
    END
  END r0_rd_out[81]
  PIN r0_rd_out[82]
    DIRECTION OUTPUT ;
    USE SIGNAL ;
    SHAPE ABUTMENT ;
    PORT
      LAYER M3 ;
      RECT 71.055 146.827 71.073 146.881 ;
    END
  END r0_rd_out[82]
  PIN r0_rd_out[83]
    DIRECTION OUTPUT ;
    USE SIGNAL ;
    SHAPE ABUTMENT ;
    PORT
      LAYER M3 ;
      RECT 71.919 146.827 71.937 146.881 ;
    END
  END r0_rd_out[83]
  PIN r0_rd_out[84]
    DIRECTION OUTPUT ;
    USE SIGNAL ;
    SHAPE ABUTMENT ;
    PORT
      LAYER M3 ;
      RECT 72.783 146.827 72.801 146.881 ;
    END
  END r0_rd_out[84]
  PIN r0_rd_out[85]
    DIRECTION OUTPUT ;
    USE SIGNAL ;
    SHAPE ABUTMENT ;
    PORT
      LAYER M3 ;
      RECT 73.647 146.827 73.665 146.881 ;
    END
  END r0_rd_out[85]
  PIN r0_rd_out[86]
    DIRECTION OUTPUT ;
    USE SIGNAL ;
    SHAPE ABUTMENT ;
    PORT
      LAYER M3 ;
      RECT 74.511 146.827 74.529 146.881 ;
    END
  END r0_rd_out[86]
  PIN r0_rd_out[87]
    DIRECTION OUTPUT ;
    USE SIGNAL ;
    SHAPE ABUTMENT ;
    PORT
      LAYER M3 ;
      RECT 75.375 146.827 75.393 146.881 ;
    END
  END r0_rd_out[87]
  PIN r0_rd_out[88]
    DIRECTION OUTPUT ;
    USE SIGNAL ;
    SHAPE ABUTMENT ;
    PORT
      LAYER M3 ;
      RECT 76.239 146.827 76.257 146.881 ;
    END
  END r0_rd_out[88]
  PIN r0_rd_out[89]
    DIRECTION OUTPUT ;
    USE SIGNAL ;
    SHAPE ABUTMENT ;
    PORT
      LAYER M3 ;
      RECT 77.103 146.827 77.121 146.881 ;
    END
  END r0_rd_out[89]
  PIN r0_rd_out[90]
    DIRECTION OUTPUT ;
    USE SIGNAL ;
    SHAPE ABUTMENT ;
    PORT
      LAYER M3 ;
      RECT 77.967 146.827 77.985 146.881 ;
    END
  END r0_rd_out[90]
  PIN r0_rd_out[91]
    DIRECTION OUTPUT ;
    USE SIGNAL ;
    SHAPE ABUTMENT ;
    PORT
      LAYER M3 ;
      RECT 78.831 146.827 78.849 146.881 ;
    END
  END r0_rd_out[91]
  PIN rw0_addr_in[0]
    DIRECTION INPUT ;
    USE SIGNAL ;
    SHAPE ABUTMENT ;
    PORT
      LAYER M4 ;
      RECT 0.000 108.468 0.072 108.492 ;
    END
  END rw0_addr_in[0]
  PIN rw0_addr_in[1]
    DIRECTION INPUT ;
    USE SIGNAL ;
    SHAPE ABUTMENT ;
    PORT
      LAYER M4 ;
      RECT 0.000 113.172 0.072 113.196 ;
    END
  END rw0_addr_in[1]
  PIN rw0_addr_in[2]
    DIRECTION INPUT ;
    USE SIGNAL ;
    SHAPE ABUTMENT ;
    PORT
      LAYER M4 ;
      RECT 0.000 117.876 0.072 117.900 ;
    END
  END rw0_addr_in[2]
  PIN rw0_addr_in[3]
    DIRECTION INPUT ;
    USE SIGNAL ;
    SHAPE ABUTMENT ;
    PORT
      LAYER M4 ;
      RECT 0.000 122.580 0.072 122.604 ;
    END
  END rw0_addr_in[3]
  PIN rw0_addr_in[4]
    DIRECTION INPUT ;
    USE SIGNAL ;
    SHAPE ABUTMENT ;
    PORT
      LAYER M4 ;
      RECT 84.384 108.468 84.456 108.492 ;
    END
  END rw0_addr_in[4]
  PIN rw0_addr_in[5]
    DIRECTION INPUT ;
    USE SIGNAL ;
    SHAPE ABUTMENT ;
    PORT
      LAYER M4 ;
      RECT 84.384 113.172 84.456 113.196 ;
    END
  END rw0_addr_in[5]
  PIN rw0_addr_in[6]
    DIRECTION INPUT ;
    USE SIGNAL ;
    SHAPE ABUTMENT ;
    PORT
      LAYER M4 ;
      RECT 84.384 117.876 84.456 117.900 ;
    END
  END rw0_addr_in[6]
  PIN rw0_addr_in[7]
    DIRECTION INPUT ;
    USE SIGNAL ;
    SHAPE ABUTMENT ;
    PORT
      LAYER M4 ;
      RECT 84.384 122.580 84.456 122.604 ;
    END
  END rw0_addr_in[7]
  PIN r0_addr_in[0]
    DIRECTION INPUT ;
    USE SIGNAL ;
    SHAPE ABUTMENT ;
    PORT
      LAYER M4 ;
      RECT 0.000 127.284 0.072 127.308 ;
    END
  END r0_addr_in[0]
  PIN r0_addr_in[1]
    DIRECTION INPUT ;
    USE SIGNAL ;
    SHAPE ABUTMENT ;
    PORT
      LAYER M4 ;
      RECT 0.000 131.988 0.072 132.012 ;
    END
  END r0_addr_in[1]
  PIN r0_addr_in[2]
    DIRECTION INPUT ;
    USE SIGNAL ;
    SHAPE ABUTMENT ;
    PORT
      LAYER M4 ;
      RECT 0.000 136.692 0.072 136.716 ;
    END
  END r0_addr_in[2]
  PIN r0_addr_in[3]
    DIRECTION INPUT ;
    USE SIGNAL ;
    SHAPE ABUTMENT ;
    PORT
      LAYER M4 ;
      RECT 0.000 141.396 0.072 141.420 ;
    END
  END r0_addr_in[3]
  PIN r0_addr_in[4]
    DIRECTION INPUT ;
    USE SIGNAL ;
    SHAPE ABUTMENT ;
    PORT
      LAYER M4 ;
      RECT 84.384 127.284 84.456 127.308 ;
    END
  END r0_addr_in[4]
  PIN r0_addr_in[5]
    DIRECTION INPUT ;
    USE SIGNAL ;
    SHAPE ABUTMENT ;
    PORT
      LAYER M4 ;
      RECT 84.384 131.988 84.456 132.012 ;
    END
  END r0_addr_in[5]
  PIN r0_addr_in[6]
    DIRECTION INPUT ;
    USE SIGNAL ;
    SHAPE ABUTMENT ;
    PORT
      LAYER M4 ;
      RECT 84.384 136.692 84.456 136.716 ;
    END
  END r0_addr_in[6]
  PIN r0_addr_in[7]
    DIRECTION INPUT ;
    USE SIGNAL ;
    SHAPE ABUTMENT ;
    PORT
      LAYER M4 ;
      RECT 84.384 141.396 84.456 141.420 ;
    END
  END r0_addr_in[7]
  PIN rw0_we_in
    DIRECTION INPUT ;
    USE SIGNAL ;
    SHAPE ABUTMENT ;
    PORT
      LAYER M3 ;
      RECT 79.695 146.827 79.713 146.881 ;
    END
  END rw0_we_in
  PIN rw0_ce_in
    DIRECTION INPUT ;
    USE SIGNAL ;
    SHAPE ABUTMENT ;
    PORT
      LAYER M3 ;
      RECT 80.559 146.827 80.577 146.881 ;
    END
  END rw0_ce_in
  PIN rw0_clk
    DIRECTION INPUT ;
    USE SIGNAL ;
    SHAPE ABUTMENT ;
    PORT
      LAYER M3 ;
      RECT 81.423 146.827 81.441 146.881 ;
    END
  END rw0_clk
  PIN r0_ce_in
    DIRECTION INPUT ;
    USE SIGNAL ;
    SHAPE ABUTMENT ;
    PORT
      LAYER M3 ;
      RECT 82.287 146.827 82.305 146.881 ;
    END
  END r0_ce_in
  PIN r0_clk
    DIRECTION INPUT ;
    USE SIGNAL ;
    SHAPE ABUTMENT ;
    PORT
      LAYER M3 ;
      RECT 83.151 146.827 83.169 146.881 ;
    END
  END r0_clk
  PIN VSS
    DIRECTION INOUT ;
    USE GROUND ;
    PORT
      LAYER M4 ;
      RECT 0.216 0.240 84.240 0.336 ;
      RECT 0.216 1.008 84.240 1.104 ;
      RECT 0.216 1.776 84.240 1.872 ;
      RECT 0.216 2.544 84.240 2.640 ;
      RECT 0.216 3.312 84.240 3.408 ;
      RECT 0.216 4.080 84.240 4.176 ;
      RECT 0.216 4.848 84.240 4.944 ;
      RECT 0.216 5.616 84.240 5.712 ;
      RECT 0.216 6.384 84.240 6.480 ;
      RECT 0.216 7.152 84.240 7.248 ;
      RECT 0.216 7.920 84.240 8.016 ;
      RECT 0.216 8.688 84.240 8.784 ;
      RECT 0.216 9.456 84.240 9.552 ;
      RECT 0.216 10.224 84.240 10.320 ;
      RECT 0.216 10.992 84.240 11.088 ;
      RECT 0.216 11.760 84.240 11.856 ;
      RECT 0.216 12.528 84.240 12.624 ;
      RECT 0.216 13.296 84.240 13.392 ;
      RECT 0.216 14.064 84.240 14.160 ;
      RECT 0.216 14.832 84.240 14.928 ;
      RECT 0.216 15.600 84.240 15.696 ;
      RECT 0.216 16.368 84.240 16.464 ;
      RECT 0.216 17.136 84.240 17.232 ;
      RECT 0.216 17.904 84.240 18.000 ;
      RECT 0.216 18.672 84.240 18.768 ;
      RECT 0.216 19.440 84.240 19.536 ;
      RECT 0.216 20.208 84.240 20.304 ;
      RECT 0.216 20.976 84.240 21.072 ;
      RECT 0.216 21.744 84.240 21.840 ;
      RECT 0.216 22.512 84.240 22.608 ;
      RECT 0.216 23.280 84.240 23.376 ;
      RECT 0.216 24.048 84.240 24.144 ;
      RECT 0.216 24.816 84.240 24.912 ;
      RECT 0.216 25.584 84.240 25.680 ;
      RECT 0.216 26.352 84.240 26.448 ;
      RECT 0.216 27.120 84.240 27.216 ;
      RECT 0.216 27.888 84.240 27.984 ;
      RECT 0.216 28.656 84.240 28.752 ;
      RECT 0.216 29.424 84.240 29.520 ;
      RECT 0.216 30.192 84.240 30.288 ;
      RECT 0.216 30.960 84.240 31.056 ;
      RECT 0.216 31.728 84.240 31.824 ;
      RECT 0.216 32.496 84.240 32.592 ;
      RECT 0.216 33.264 84.240 33.360 ;
      RECT 0.216 34.032 84.240 34.128 ;
      RECT 0.216 34.800 84.240 34.896 ;
      RECT 0.216 35.568 84.240 35.664 ;
      RECT 0.216 36.336 84.240 36.432 ;
      RECT 0.216 37.104 84.240 37.200 ;
      RECT 0.216 37.872 84.240 37.968 ;
      RECT 0.216 38.640 84.240 38.736 ;
      RECT 0.216 39.408 84.240 39.504 ;
      RECT 0.216 40.176 84.240 40.272 ;
      RECT 0.216 40.944 84.240 41.040 ;
      RECT 0.216 41.712 84.240 41.808 ;
      RECT 0.216 42.480 84.240 42.576 ;
      RECT 0.216 43.248 84.240 43.344 ;
      RECT 0.216 44.016 84.240 44.112 ;
      RECT 0.216 44.784 84.240 44.880 ;
      RECT 0.216 45.552 84.240 45.648 ;
      RECT 0.216 46.320 84.240 46.416 ;
      RECT 0.216 47.088 84.240 47.184 ;
      RECT 0.216 47.856 84.240 47.952 ;
      RECT 0.216 48.624 84.240 48.720 ;
      RECT 0.216 49.392 84.240 49.488 ;
      RECT 0.216 50.160 84.240 50.256 ;
      RECT 0.216 50.928 84.240 51.024 ;
      RECT 0.216 51.696 84.240 51.792 ;
      RECT 0.216 52.464 84.240 52.560 ;
      RECT 0.216 53.232 84.240 53.328 ;
      RECT 0.216 54.000 84.240 54.096 ;
      RECT 0.216 54.768 84.240 54.864 ;
      RECT 0.216 55.536 84.240 55.632 ;
      RECT 0.216 56.304 84.240 56.400 ;
      RECT 0.216 57.072 84.240 57.168 ;
      RECT 0.216 57.840 84.240 57.936 ;
      RECT 0.216 58.608 84.240 58.704 ;
      RECT 0.216 59.376 84.240 59.472 ;
      RECT 0.216 60.144 84.240 60.240 ;
      RECT 0.216 60.912 84.240 61.008 ;
      RECT 0.216 61.680 84.240 61.776 ;
      RECT 0.216 62.448 84.240 62.544 ;
      RECT 0.216 63.216 84.240 63.312 ;
      RECT 0.216 63.984 84.240 64.080 ;
      RECT 0.216 64.752 84.240 64.848 ;
      RECT 0.216 65.520 84.240 65.616 ;
      RECT 0.216 66.288 84.240 66.384 ;
      RECT 0.216 67.056 84.240 67.152 ;
      RECT 0.216 67.824 84.240 67.920 ;
      RECT 0.216 68.592 84.240 68.688 ;
      RECT 0.216 69.360 84.240 69.456 ;
      RECT 0.216 70.128 84.240 70.224 ;
      RECT 0.216 70.896 84.240 70.992 ;
      RECT 0.216 71.664 84.240 71.760 ;
      RECT 0.216 72.432 84.240 72.528 ;
      RECT 0.216 73.200 84.240 73.296 ;
      RECT 0.216 73.968 84.240 74.064 ;
      RECT 0.216 74.736 84.240 74.832 ;
      RECT 0.216 75.504 84.240 75.600 ;
      RECT 0.216 76.272 84.240 76.368 ;
      RECT 0.216 77.040 84.240 77.136 ;
      RECT 0.216 77.808 84.240 77.904 ;
      RECT 0.216 78.576 84.240 78.672 ;
      RECT 0.216 79.344 84.240 79.440 ;
      RECT 0.216 80.112 84.240 80.208 ;
      RECT 0.216 80.880 84.240 80.976 ;
      RECT 0.216 81.648 84.240 81.744 ;
      RECT 0.216 82.416 84.240 82.512 ;
      RECT 0.216 83.184 84.240 83.280 ;
      RECT 0.216 83.952 84.240 84.048 ;
      RECT 0.216 84.720 84.240 84.816 ;
      RECT 0.216 85.488 84.240 85.584 ;
      RECT 0.216 86.256 84.240 86.352 ;
      RECT 0.216 87.024 84.240 87.120 ;
      RECT 0.216 87.792 84.240 87.888 ;
      RECT 0.216 88.560 84.240 88.656 ;
      RECT 0.216 89.328 84.240 89.424 ;
      RECT 0.216 90.096 84.240 90.192 ;
      RECT 0.216 90.864 84.240 90.960 ;
      RECT 0.216 91.632 84.240 91.728 ;
      RECT 0.216 92.400 84.240 92.496 ;
      RECT 0.216 93.168 84.240 93.264 ;
      RECT 0.216 93.936 84.240 94.032 ;
      RECT 0.216 94.704 84.240 94.800 ;
      RECT 0.216 95.472 84.240 95.568 ;
      RECT 0.216 96.240 84.240 96.336 ;
      RECT 0.216 97.008 84.240 97.104 ;
      RECT 0.216 97.776 84.240 97.872 ;
      RECT 0.216 98.544 84.240 98.640 ;
      RECT 0.216 99.312 84.240 99.408 ;
      RECT 0.216 100.080 84.240 100.176 ;
      RECT 0.216 100.848 84.240 100.944 ;
      RECT 0.216 101.616 84.240 101.712 ;
      RECT 0.216 102.384 84.240 102.480 ;
      RECT 0.216 103.152 84.240 103.248 ;
      RECT 0.216 103.920 84.240 104.016 ;
      RECT 0.216 104.688 84.240 104.784 ;
      RECT 0.216 105.456 84.240 105.552 ;
      RECT 0.216 106.224 84.240 106.320 ;
      RECT 0.216 106.992 84.240 107.088 ;
      RECT 0.216 107.760 84.240 107.856 ;
      RECT 0.216 108.528 84.240 108.624 ;
      RECT 0.216 109.296 84.240 109.392 ;
      RECT 0.216 110.064 84.240 110.160 ;
      RECT 0.216 110.832 84.240 110.928 ;
      RECT 0.216 111.600 84.240 111.696 ;
      RECT 0.216 112.368 84.240 112.464 ;
      RECT 0.216 113.136 84.240 113.232 ;
      RECT 0.216 113.904 84.240 114.000 ;
      RECT 0.216 114.672 84.240 114.768 ;
      RECT 0.216 115.440 84.240 115.536 ;
      RECT 0.216 116.208 84.240 116.304 ;
      RECT 0.216 116.976 84.240 117.072 ;
      RECT 0.216 117.744 84.240 117.840 ;
      RECT 0.216 118.512 84.240 118.608 ;
      RECT 0.216 119.280 84.240 119.376 ;
      RECT 0.216 120.048 84.240 120.144 ;
      RECT 0.216 120.816 84.240 120.912 ;
      RECT 0.216 121.584 84.240 121.680 ;
      RECT 0.216 122.352 84.240 122.448 ;
      RECT 0.216 123.120 84.240 123.216 ;
      RECT 0.216 123.888 84.240 123.984 ;
      RECT 0.216 124.656 84.240 124.752 ;
      RECT 0.216 125.424 84.240 125.520 ;
      RECT 0.216 126.192 84.240 126.288 ;
      RECT 0.216 126.960 84.240 127.056 ;
      RECT 0.216 127.728 84.240 127.824 ;
      RECT 0.216 128.496 84.240 128.592 ;
      RECT 0.216 129.264 84.240 129.360 ;
      RECT 0.216 130.032 84.240 130.128 ;
      RECT 0.216 130.800 84.240 130.896 ;
      RECT 0.216 131.568 84.240 131.664 ;
      RECT 0.216 132.336 84.240 132.432 ;
      RECT 0.216 133.104 84.240 133.200 ;
      RECT 0.216 133.872 84.240 133.968 ;
      RECT 0.216 134.640 84.240 134.736 ;
      RECT 0.216 135.408 84.240 135.504 ;
      RECT 0.216 136.176 84.240 136.272 ;
      RECT 0.216 136.944 84.240 137.040 ;
      RECT 0.216 137.712 84.240 137.808 ;
      RECT 0.216 138.480 84.240 138.576 ;
      RECT 0.216 139.248 84.240 139.344 ;
      RECT 0.216 140.016 84.240 140.112 ;
      RECT 0.216 140.784 84.240 140.880 ;
      RECT 0.216 141.552 84.240 141.648 ;
      RECT 0.216 142.320 84.240 142.416 ;
      RECT 0.216 143.088 84.240 143.184 ;
      RECT 0.216 143.856 84.240 143.952 ;
      RECT 0.216 144.624 84.240 144.720 ;
      RECT 0.216 145.392 84.240 145.488 ;
      RECT 0.216 146.160 84.240 146.256 ;
    END
  END VSS
  PIN VDD
    DIRECTION INOUT ;
    USE POWER ;
    PORT
      LAYER M4 ;
      RECT 0.216 0.624 84.240 0.720 ;
      RECT 0.216 1.392 84.240 1.488 ;
      RECT 0.216 2.160 84.240 2.256 ;
      RECT 0.216 2.928 84.240 3.024 ;
      RECT 0.216 3.696 84.240 3.792 ;
      RECT 0.216 4.464 84.240 4.560 ;
      RECT 0.216 5.232 84.240 5.328 ;
      RECT 0.216 6.000 84.240 6.096 ;
      RECT 0.216 6.768 84.240 6.864 ;
      RECT 0.216 7.536 84.240 7.632 ;
      RECT 0.216 8.304 84.240 8.400 ;
      RECT 0.216 9.072 84.240 9.168 ;
      RECT 0.216 9.840 84.240 9.936 ;
      RECT 0.216 10.608 84.240 10.704 ;
      RECT 0.216 11.376 84.240 11.472 ;
      RECT 0.216 12.144 84.240 12.240 ;
      RECT 0.216 12.912 84.240 13.008 ;
      RECT 0.216 13.680 84.240 13.776 ;
      RECT 0.216 14.448 84.240 14.544 ;
      RECT 0.216 15.216 84.240 15.312 ;
      RECT 0.216 15.984 84.240 16.080 ;
      RECT 0.216 16.752 84.240 16.848 ;
      RECT 0.216 17.520 84.240 17.616 ;
      RECT 0.216 18.288 84.240 18.384 ;
      RECT 0.216 19.056 84.240 19.152 ;
      RECT 0.216 19.824 84.240 19.920 ;
      RECT 0.216 20.592 84.240 20.688 ;
      RECT 0.216 21.360 84.240 21.456 ;
      RECT 0.216 22.128 84.240 22.224 ;
      RECT 0.216 22.896 84.240 22.992 ;
      RECT 0.216 23.664 84.240 23.760 ;
      RECT 0.216 24.432 84.240 24.528 ;
      RECT 0.216 25.200 84.240 25.296 ;
      RECT 0.216 25.968 84.240 26.064 ;
      RECT 0.216 26.736 84.240 26.832 ;
      RECT 0.216 27.504 84.240 27.600 ;
      RECT 0.216 28.272 84.240 28.368 ;
      RECT 0.216 29.040 84.240 29.136 ;
      RECT 0.216 29.808 84.240 29.904 ;
      RECT 0.216 30.576 84.240 30.672 ;
      RECT 0.216 31.344 84.240 31.440 ;
      RECT 0.216 32.112 84.240 32.208 ;
      RECT 0.216 32.880 84.240 32.976 ;
      RECT 0.216 33.648 84.240 33.744 ;
      RECT 0.216 34.416 84.240 34.512 ;
      RECT 0.216 35.184 84.240 35.280 ;
      RECT 0.216 35.952 84.240 36.048 ;
      RECT 0.216 36.720 84.240 36.816 ;
      RECT 0.216 37.488 84.240 37.584 ;
      RECT 0.216 38.256 84.240 38.352 ;
      RECT 0.216 39.024 84.240 39.120 ;
      RECT 0.216 39.792 84.240 39.888 ;
      RECT 0.216 40.560 84.240 40.656 ;
      RECT 0.216 41.328 84.240 41.424 ;
      RECT 0.216 42.096 84.240 42.192 ;
      RECT 0.216 42.864 84.240 42.960 ;
      RECT 0.216 43.632 84.240 43.728 ;
      RECT 0.216 44.400 84.240 44.496 ;
      RECT 0.216 45.168 84.240 45.264 ;
      RECT 0.216 45.936 84.240 46.032 ;
      RECT 0.216 46.704 84.240 46.800 ;
      RECT 0.216 47.472 84.240 47.568 ;
      RECT 0.216 48.240 84.240 48.336 ;
      RECT 0.216 49.008 84.240 49.104 ;
      RECT 0.216 49.776 84.240 49.872 ;
      RECT 0.216 50.544 84.240 50.640 ;
      RECT 0.216 51.312 84.240 51.408 ;
      RECT 0.216 52.080 84.240 52.176 ;
      RECT 0.216 52.848 84.240 52.944 ;
      RECT 0.216 53.616 84.240 53.712 ;
      RECT 0.216 54.384 84.240 54.480 ;
      RECT 0.216 55.152 84.240 55.248 ;
      RECT 0.216 55.920 84.240 56.016 ;
      RECT 0.216 56.688 84.240 56.784 ;
      RECT 0.216 57.456 84.240 57.552 ;
      RECT 0.216 58.224 84.240 58.320 ;
      RECT 0.216 58.992 84.240 59.088 ;
      RECT 0.216 59.760 84.240 59.856 ;
      RECT 0.216 60.528 84.240 60.624 ;
      RECT 0.216 61.296 84.240 61.392 ;
      RECT 0.216 62.064 84.240 62.160 ;
      RECT 0.216 62.832 84.240 62.928 ;
      RECT 0.216 63.600 84.240 63.696 ;
      RECT 0.216 64.368 84.240 64.464 ;
      RECT 0.216 65.136 84.240 65.232 ;
      RECT 0.216 65.904 84.240 66.000 ;
      RECT 0.216 66.672 84.240 66.768 ;
      RECT 0.216 67.440 84.240 67.536 ;
      RECT 0.216 68.208 84.240 68.304 ;
      RECT 0.216 68.976 84.240 69.072 ;
      RECT 0.216 69.744 84.240 69.840 ;
      RECT 0.216 70.512 84.240 70.608 ;
      RECT 0.216 71.280 84.240 71.376 ;
      RECT 0.216 72.048 84.240 72.144 ;
      RECT 0.216 72.816 84.240 72.912 ;
      RECT 0.216 73.584 84.240 73.680 ;
      RECT 0.216 74.352 84.240 74.448 ;
      RECT 0.216 75.120 84.240 75.216 ;
      RECT 0.216 75.888 84.240 75.984 ;
      RECT 0.216 76.656 84.240 76.752 ;
      RECT 0.216 77.424 84.240 77.520 ;
      RECT 0.216 78.192 84.240 78.288 ;
      RECT 0.216 78.960 84.240 79.056 ;
      RECT 0.216 79.728 84.240 79.824 ;
      RECT 0.216 80.496 84.240 80.592 ;
      RECT 0.216 81.264 84.240 81.360 ;
      RECT 0.216 82.032 84.240 82.128 ;
      RECT 0.216 82.800 84.240 82.896 ;
      RECT 0.216 83.568 84.240 83.664 ;
      RECT 0.216 84.336 84.240 84.432 ;
      RECT 0.216 85.104 84.240 85.200 ;
      RECT 0.216 85.872 84.240 85.968 ;
      RECT 0.216 86.640 84.240 86.736 ;
      RECT 0.216 87.408 84.240 87.504 ;
      RECT 0.216 88.176 84.240 88.272 ;
      RECT 0.216 88.944 84.240 89.040 ;
      RECT 0.216 89.712 84.240 89.808 ;
      RECT 0.216 90.480 84.240 90.576 ;
      RECT 0.216 91.248 84.240 91.344 ;
      RECT 0.216 92.016 84.240 92.112 ;
      RECT 0.216 92.784 84.240 92.880 ;
      RECT 0.216 93.552 84.240 93.648 ;
      RECT 0.216 94.320 84.240 94.416 ;
      RECT 0.216 95.088 84.240 95.184 ;
      RECT 0.216 95.856 84.240 95.952 ;
      RECT 0.216 96.624 84.240 96.720 ;
      RECT 0.216 97.392 84.240 97.488 ;
      RECT 0.216 98.160 84.240 98.256 ;
      RECT 0.216 98.928 84.240 99.024 ;
      RECT 0.216 99.696 84.240 99.792 ;
      RECT 0.216 100.464 84.240 100.560 ;
      RECT 0.216 101.232 84.240 101.328 ;
      RECT 0.216 102.000 84.240 102.096 ;
      RECT 0.216 102.768 84.240 102.864 ;
      RECT 0.216 103.536 84.240 103.632 ;
      RECT 0.216 104.304 84.240 104.400 ;
      RECT 0.216 105.072 84.240 105.168 ;
      RECT 0.216 105.840 84.240 105.936 ;
      RECT 0.216 106.608 84.240 106.704 ;
      RECT 0.216 107.376 84.240 107.472 ;
      RECT 0.216 108.144 84.240 108.240 ;
      RECT 0.216 108.912 84.240 109.008 ;
      RECT 0.216 109.680 84.240 109.776 ;
      RECT 0.216 110.448 84.240 110.544 ;
      RECT 0.216 111.216 84.240 111.312 ;
      RECT 0.216 111.984 84.240 112.080 ;
      RECT 0.216 112.752 84.240 112.848 ;
      RECT 0.216 113.520 84.240 113.616 ;
      RECT 0.216 114.288 84.240 114.384 ;
      RECT 0.216 115.056 84.240 115.152 ;
      RECT 0.216 115.824 84.240 115.920 ;
      RECT 0.216 116.592 84.240 116.688 ;
      RECT 0.216 117.360 84.240 117.456 ;
      RECT 0.216 118.128 84.240 118.224 ;
      RECT 0.216 118.896 84.240 118.992 ;
      RECT 0.216 119.664 84.240 119.760 ;
      RECT 0.216 120.432 84.240 120.528 ;
      RECT 0.216 121.200 84.240 121.296 ;
      RECT 0.216 121.968 84.240 122.064 ;
      RECT 0.216 122.736 84.240 122.832 ;
      RECT 0.216 123.504 84.240 123.600 ;
      RECT 0.216 124.272 84.240 124.368 ;
      RECT 0.216 125.040 84.240 125.136 ;
      RECT 0.216 125.808 84.240 125.904 ;
      RECT 0.216 126.576 84.240 126.672 ;
      RECT 0.216 127.344 84.240 127.440 ;
      RECT 0.216 128.112 84.240 128.208 ;
      RECT 0.216 128.880 84.240 128.976 ;
      RECT 0.216 129.648 84.240 129.744 ;
      RECT 0.216 130.416 84.240 130.512 ;
      RECT 0.216 131.184 84.240 131.280 ;
      RECT 0.216 131.952 84.240 132.048 ;
      RECT 0.216 132.720 84.240 132.816 ;
      RECT 0.216 133.488 84.240 133.584 ;
      RECT 0.216 134.256 84.240 134.352 ;
      RECT 0.216 135.024 84.240 135.120 ;
      RECT 0.216 135.792 84.240 135.888 ;
      RECT 0.216 136.560 84.240 136.656 ;
      RECT 0.216 137.328 84.240 137.424 ;
      RECT 0.216 138.096 84.240 138.192 ;
      RECT 0.216 138.864 84.240 138.960 ;
      RECT 0.216 139.632 84.240 139.728 ;
      RECT 0.216 140.400 84.240 140.496 ;
      RECT 0.216 141.168 84.240 141.264 ;
      RECT 0.216 141.936 84.240 142.032 ;
      RECT 0.216 142.704 84.240 142.800 ;
      RECT 0.216 143.472 84.240 143.568 ;
      RECT 0.216 144.240 84.240 144.336 ;
      RECT 0.216 145.008 84.240 145.104 ;
      RECT 0.216 145.776 84.240 145.872 ;
      RECT 0.216 146.544 84.240 146.640 ;
    END
  END VDD
  OBS
    LAYER M1 ;
    RECT 0 0 84.456 146.881 ;
    LAYER M2 ;
    RECT 0 0 84.456 146.881 ;
    LAYER M3 ;
    RECT 0 0 84.456 146.881 ;
    LAYER M4 ;
    RECT 0 0 84.456 146.881 ;
  END
END fakeram_1rw1r_92w256d_sram

END LIBRARY
